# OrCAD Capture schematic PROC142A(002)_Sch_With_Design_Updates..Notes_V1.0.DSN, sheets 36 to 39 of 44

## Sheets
36 36. USB1 TYPE A: size C; title: USB1 TYPE-A
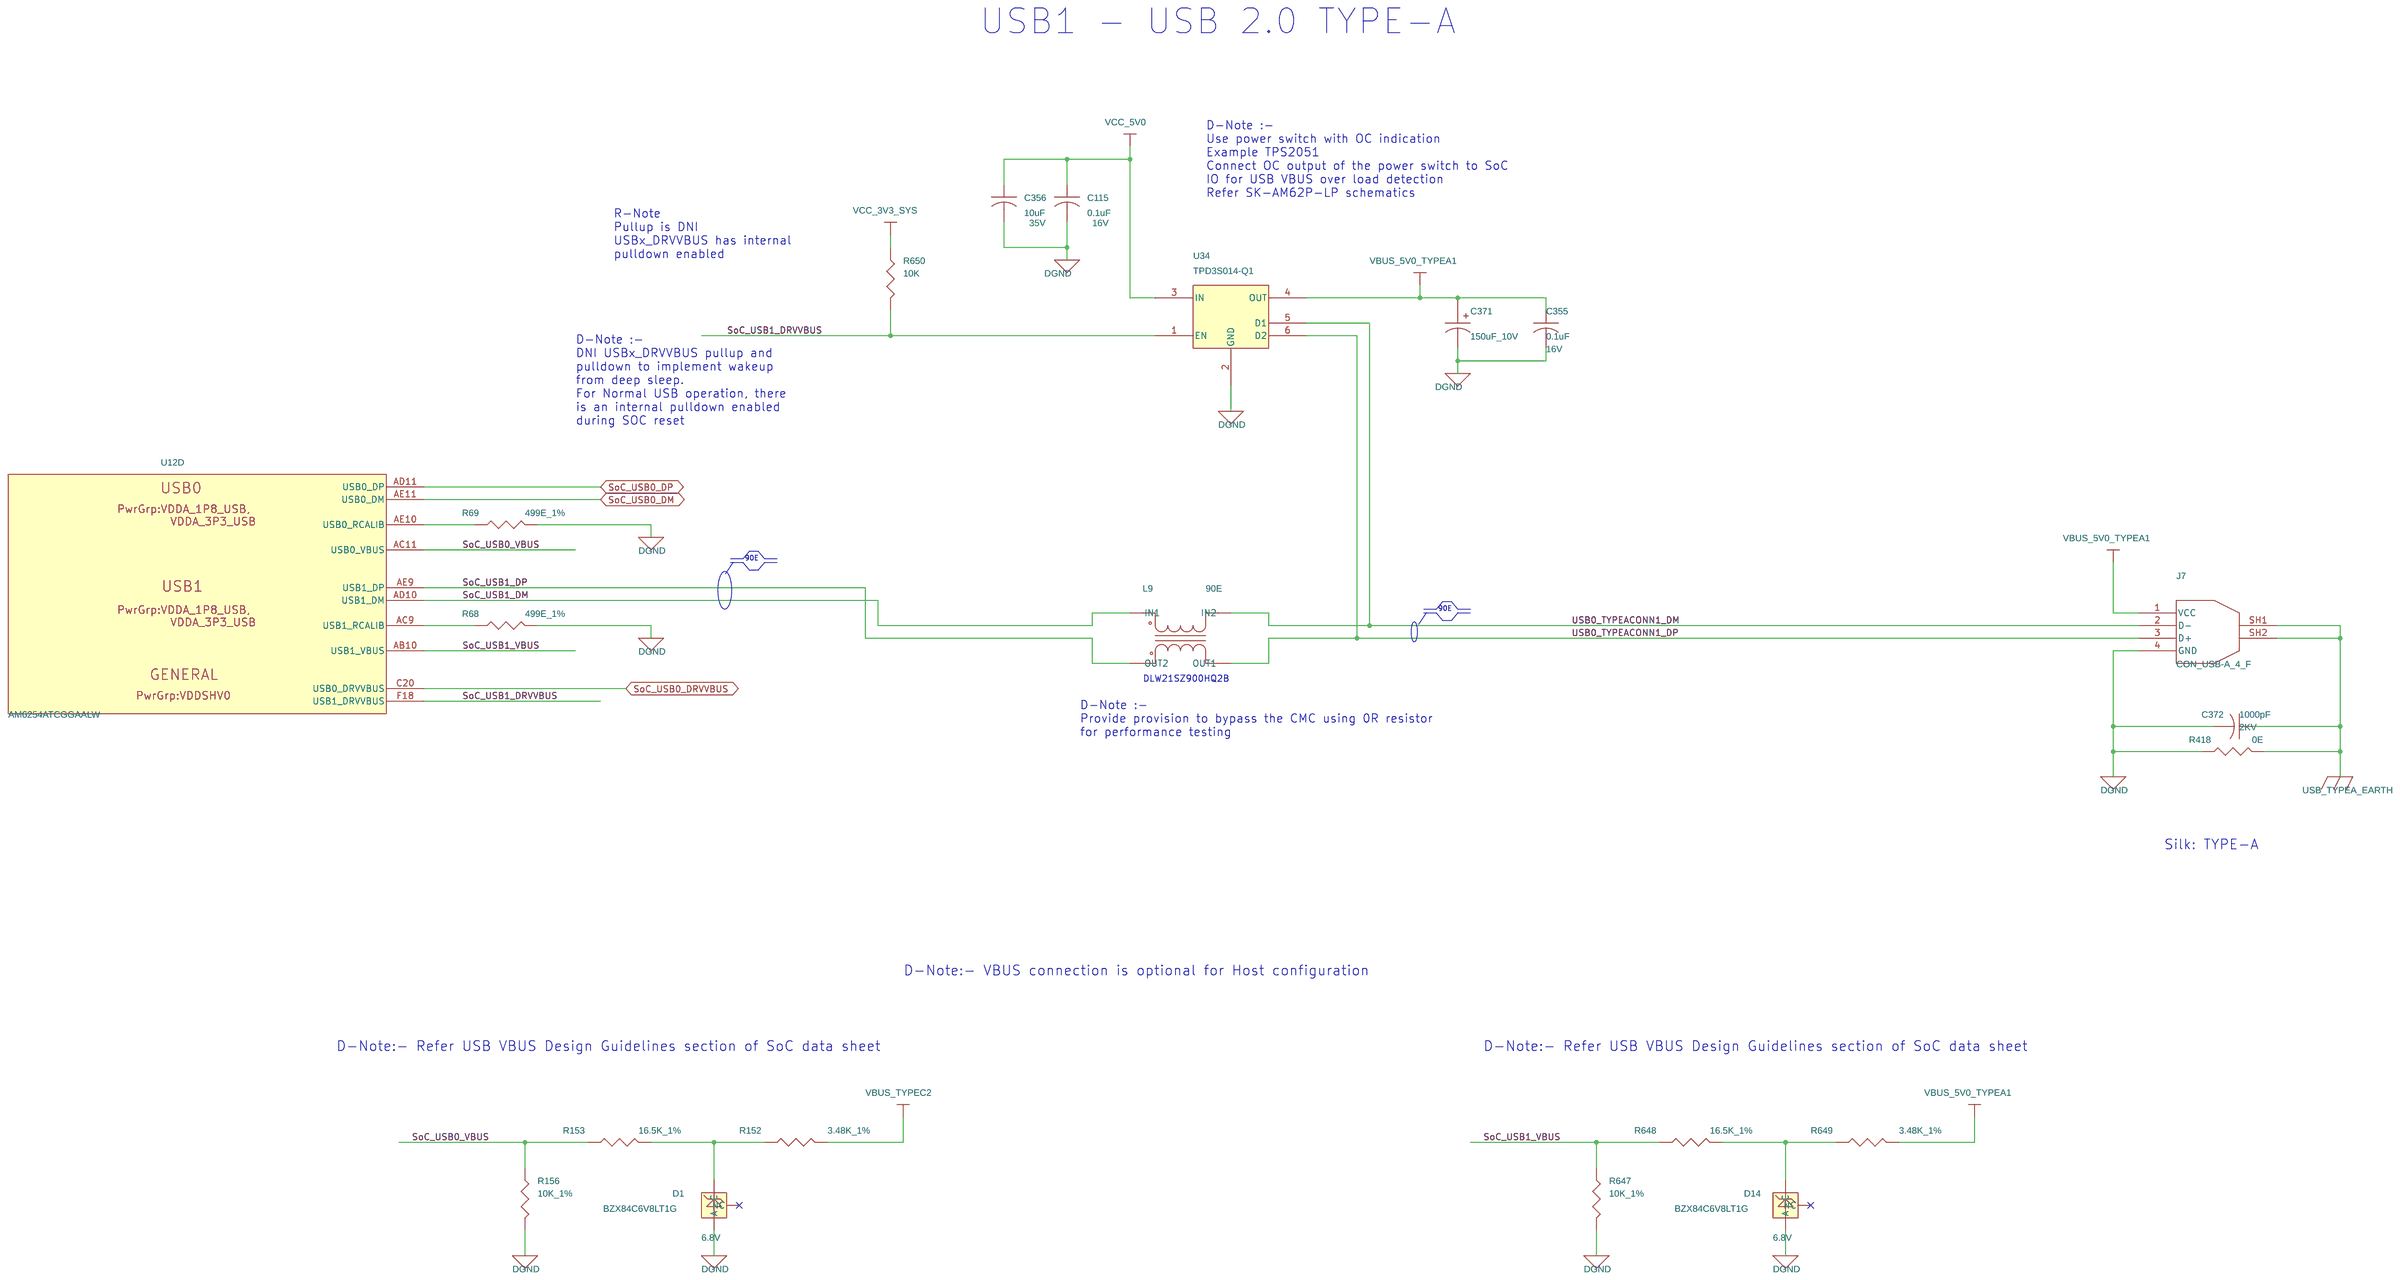
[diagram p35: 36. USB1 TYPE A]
37 37. OLDI DISPLAY INTERFACE: size C; title: OLDI DISPLAY INTERFACE
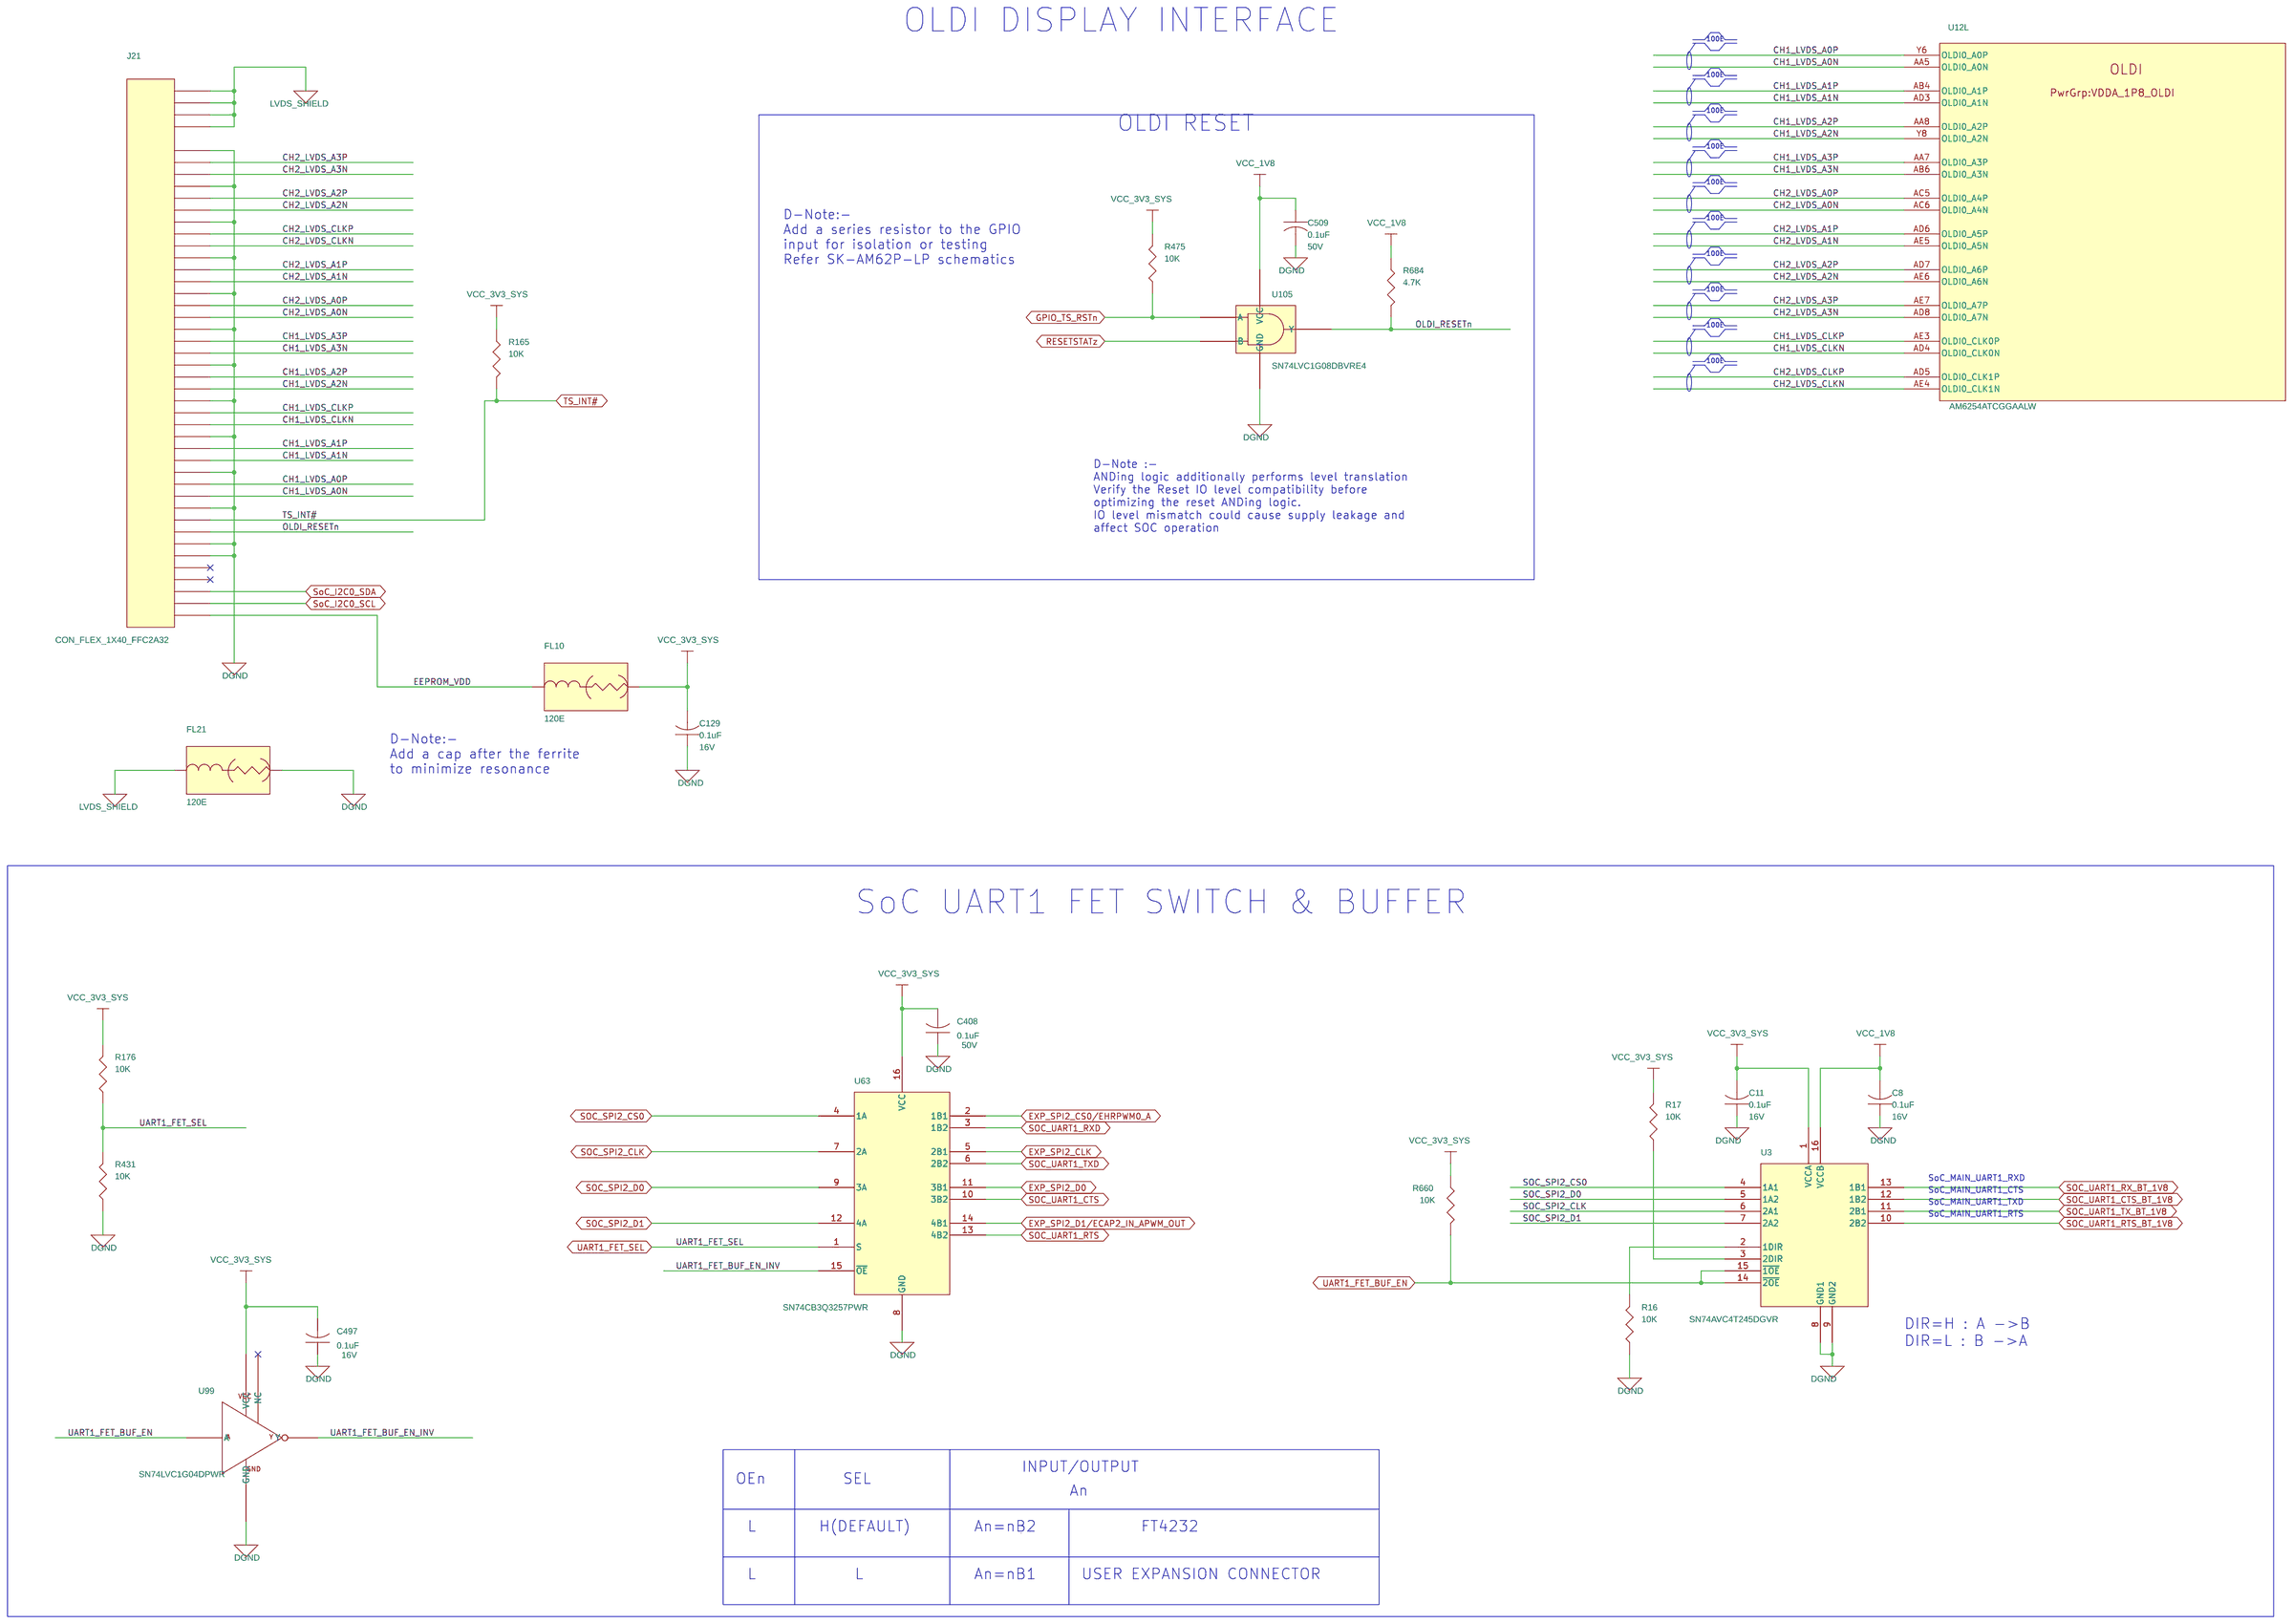
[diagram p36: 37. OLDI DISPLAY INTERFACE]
38 38. CSI INTERFACE & TEST LEDS: size C; title: CSI INTERFACE & USER TEST LEDS
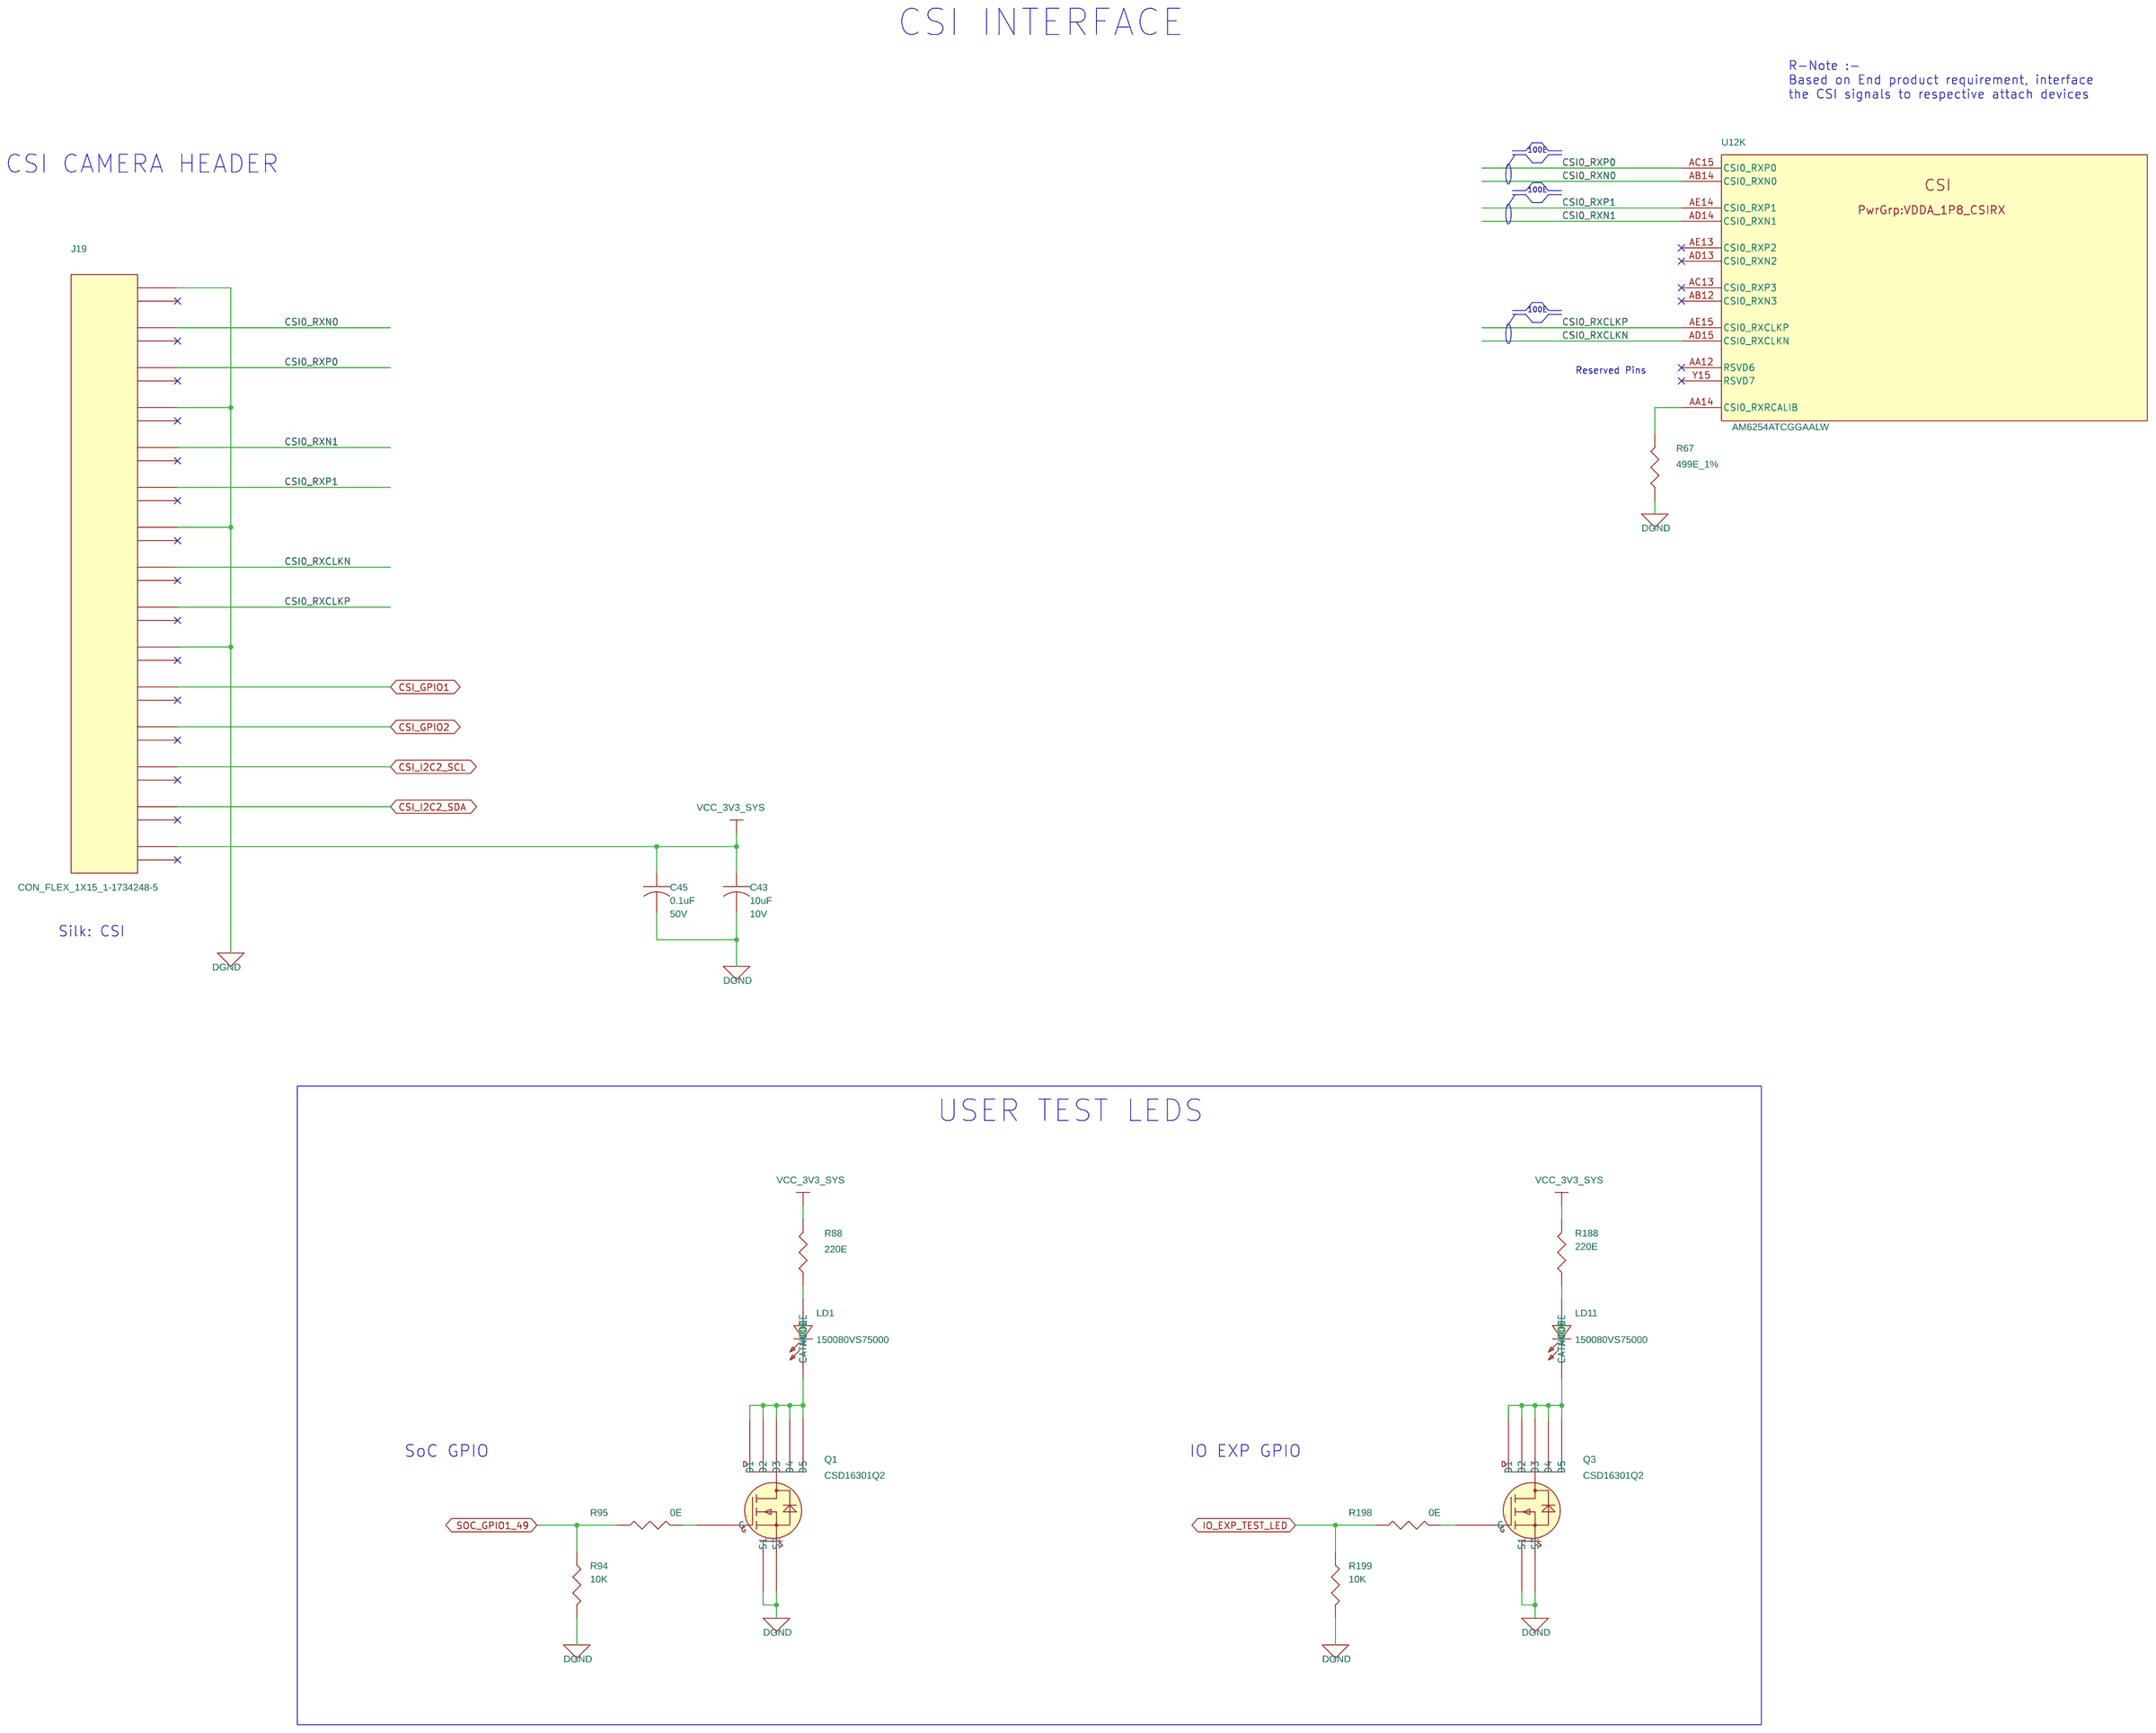
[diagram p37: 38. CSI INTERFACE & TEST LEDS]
39 39. IO EXPANDER: size C; title: IO EXPANDER

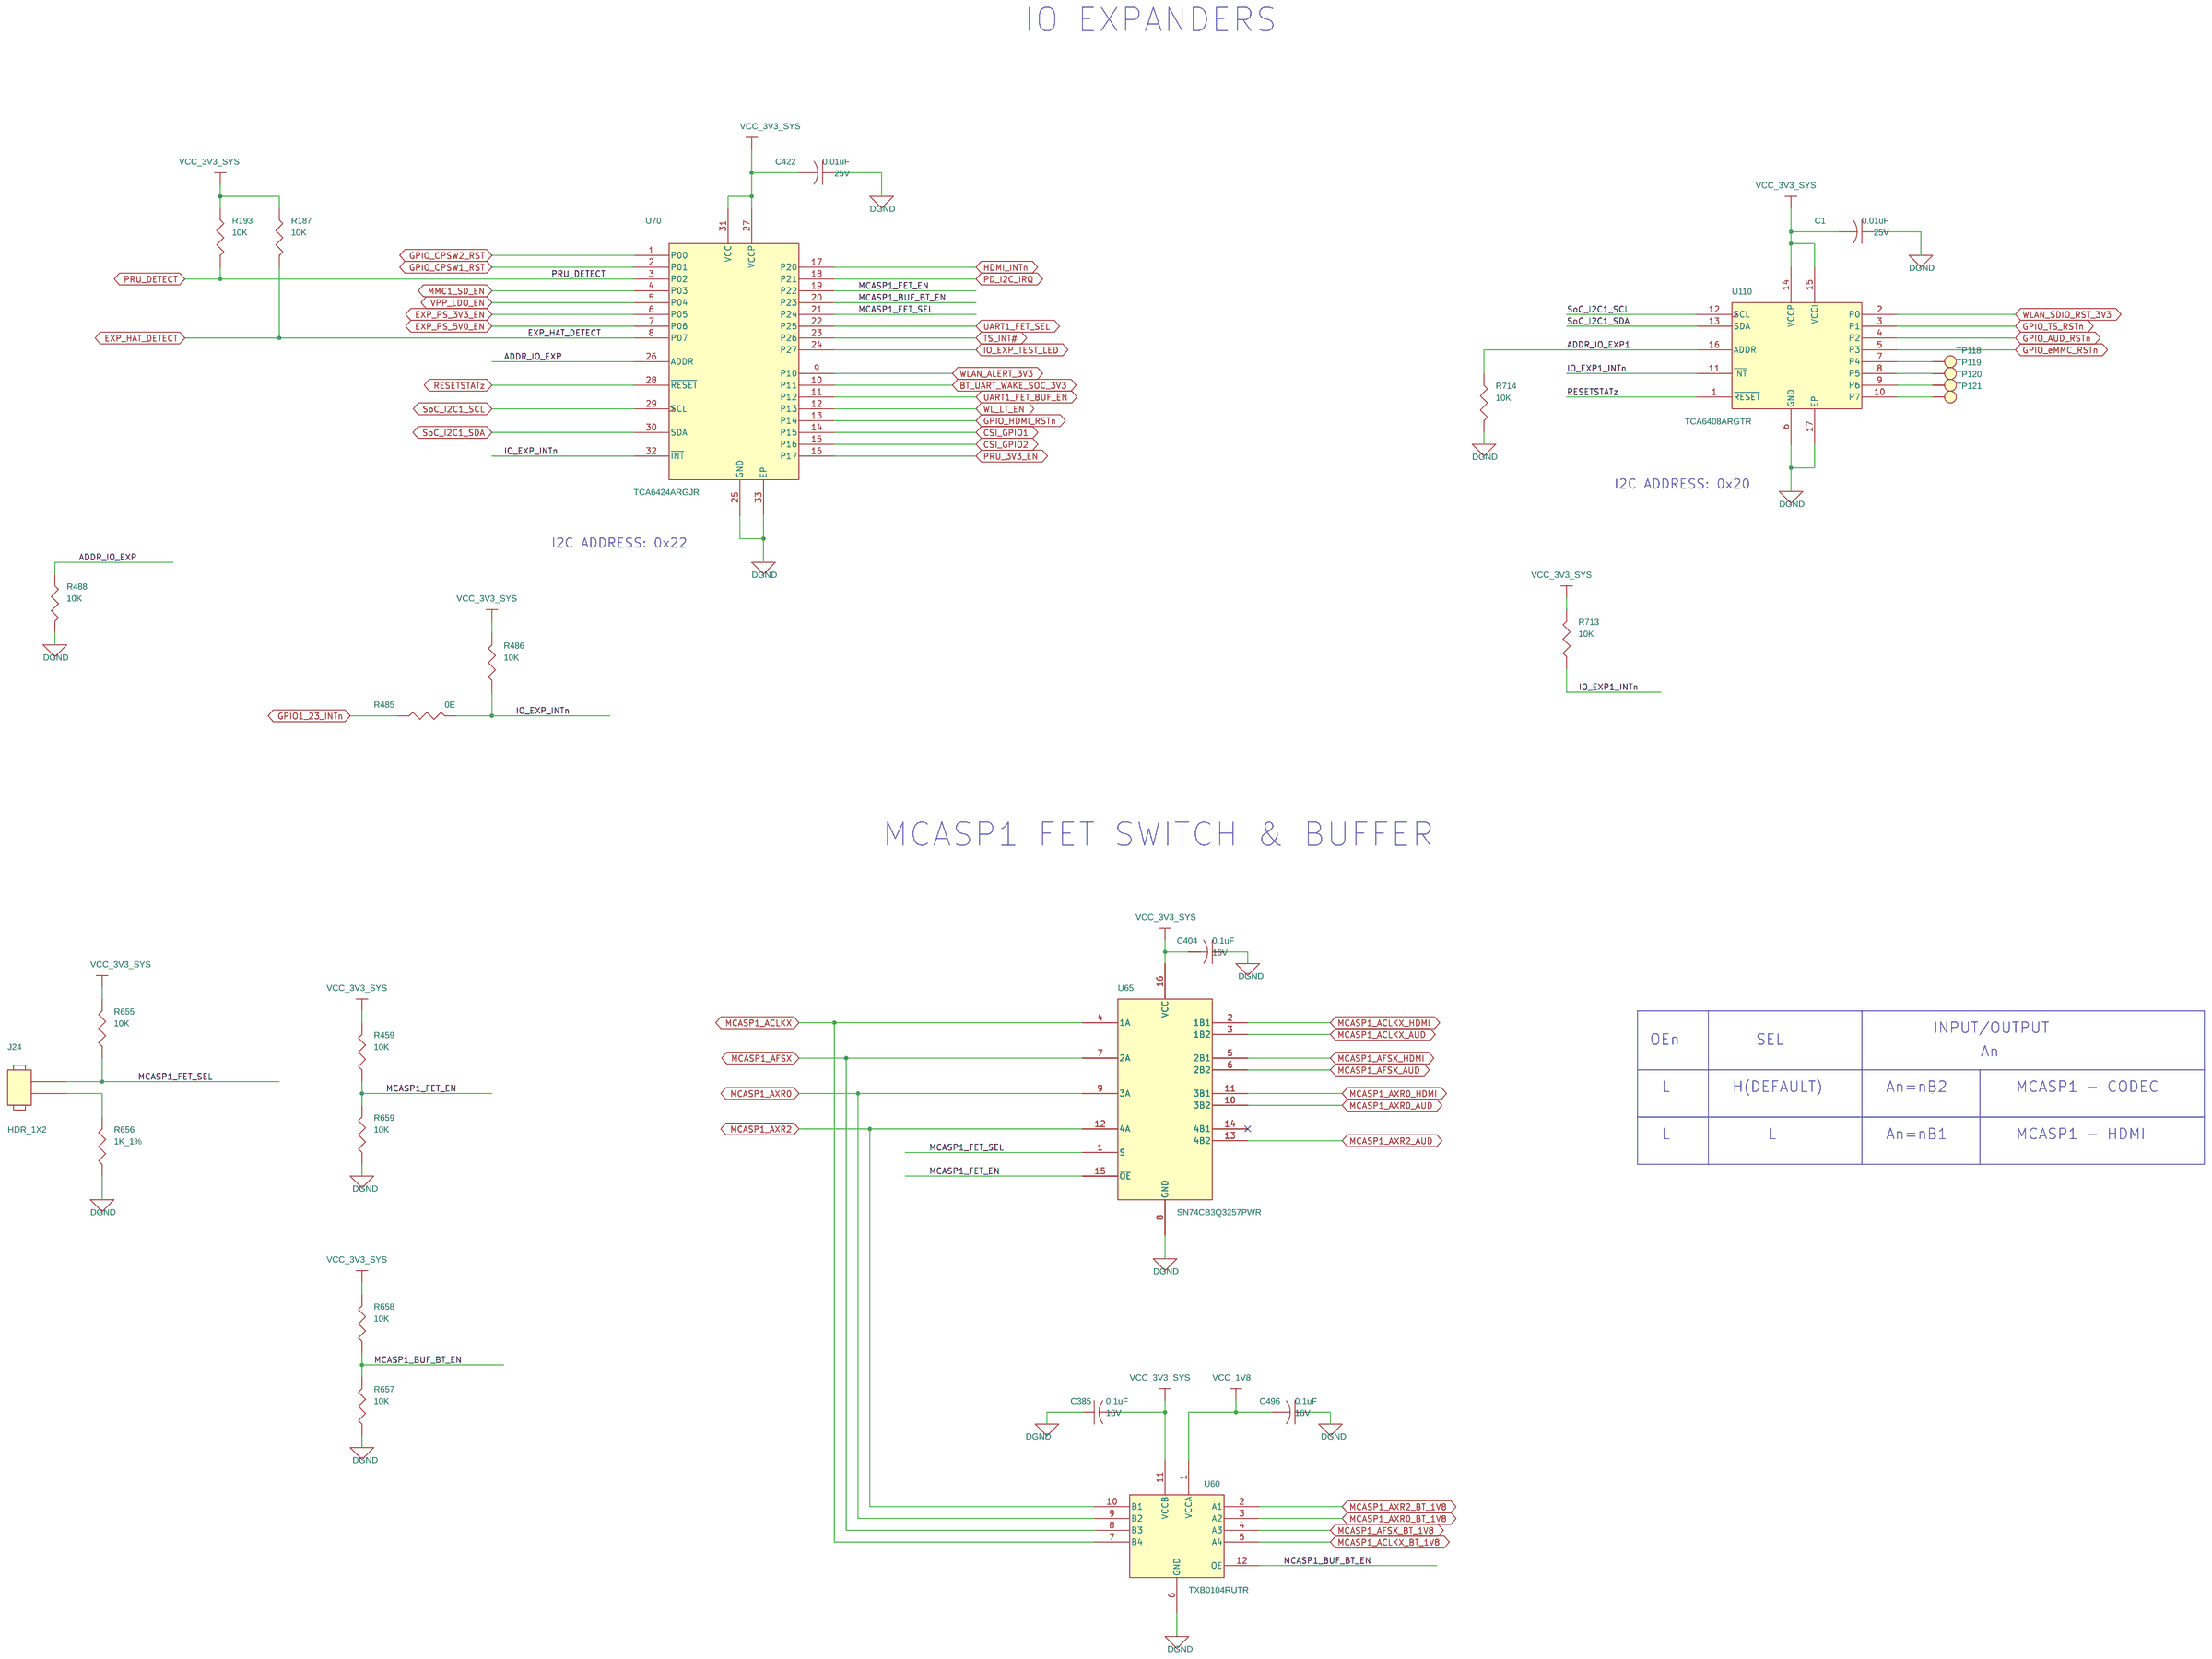
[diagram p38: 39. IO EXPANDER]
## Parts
sheet 36. USB1 TYPE A
C115  0.1uF  [CAP0201_0-5]
C355  0.1uF  [CAP0201_0-5]
C356  10uF  [CAP0603_1]
C371  150uF_10V  [CAPT7343D_3-25]
C372  1000pF  [CAP1206_1-75]
D1  BZX84C6V8LT1G  [SOT23-123_1-2]
D14  BZX84C6V8LT1G  [SOT23-123_1-2]
J7  CON_USB-A_4_F  [CON_USBA4_629104151_S_R_S_7-4]
L9  90E  [IND4_DLW21H_90X60_SMD_1-4]
R68  499E_1%  [RES0402_0-5]
R69  499E_1%  [RES0402_0-5]
R152  3.48K_1%  [RES0201_0-5]
R153  16.5K_1%  [RES0402_0-5]
R156  10K_1%  [RES0201_0-5]
R418  0E  [RES0603_0-75]
R647  10K_1%  [RES0201_0-5]
R648  16.5K_1%  [RES0402_0-5]
R649  3.48K_1%  [RES0201_0-5]
R650  10K  [RES0201_0-5]
U34  TPD3S014-Q1  [SOT23-6_1-5]
sheet 37. OLDI DISPLAY INTERFACE
C8  0.1uF  [CAP0201_0-5]
C11  0.1uF  [CAP0201_0-5]
C129  0.1uF  [CAP0201_0-5]
C408  0.1uF  [CAP0402_0-75]
C497  0.1uF  [CAP0201_0-5]
C509  0.1uF  [CAP0402_0-75]
FL10  120E  [EMIFIL_BLM15A_0402_0-6]
FL21  120E  [EMIFIL_BLM15A_0402_0-6]
J21  CON_FLEX_1X40_FFC2A32  [CON_FLEX1X40_FFC2A32-40-T_S_S_S_4-3]
R16  10K  [RES0201_0-5]
R17  10K  [RES0201_0-5]
R165  10K  [RES0201_0-5]
R176  10K  [RES0201_0-5]
R431  10K  [RES0201_0-5]
R475  10K  [RES0201_0-5]
R660  10K  [RES0201_0-5]
R684  4.7K  [RES0201_0-5]
U3  SN74AVC4T245DGVR  [TVSOP16_15-74_150X180]
U63  SN74CB3Q3257PWR  [TSSOP16_25-59_205X180]
U99  SN74LVC1G04DPWR  [X2SON5_TLV7021_30X30_0-4]
U105  SN74LVC1G08DBVRE4  [SOT23-5]
sheet 38. CSI INTERFACE & TEST LEDS
C43  10uF  [CAP0402_0-75]
C45  0.1uF  [CAP0402_0-75]
J19  CON_FLEX_1X15_1-1734248-5  [CON_FLEX1X15_1-1734248-5_S_S_S_7-7]
LD1  150080VS75000  [LED_150080VS75000_80X50_SMD_0-8]
LD11  150080VS75000  [LED_150080VS75000_80X50_SMD_0-8]
Q1  CSD16301Q2  [WSON6_CSD13202Q2_80X80_0-8]
Q3  CSD16301Q2  [WSON6_CSD13202Q2_80X80_0-8]
R67  499E_1%  [RES0402_0-5]
R88  220E  [RES0402_0-5]
R94  10K  [RES0201_0-5]
R95  0E  [RES0402_0-5]
R188  220E  [RES0402_0-5]
R198  0E  [RES0402_0-5]
R199  10K  [RES0201_0-5]
sheet 39. IO EXPANDER
C1  0.01uF  [CAP0201_0-5]
C385  0.1uF  [CAP0201_0-5]
C404  0.1uF  [CAP0201_0-5]
C422  0.01uF  [CAP0201_0-5]
C496  0.1uF  [CAP0201_0-5]
J24  HDR_1X2  [HDR_1X2_90120-0122_S_T_5-6]
R187  10K  [RES0201_0-5]
R193  10K  [RES0201_0-5]
R459  10K  [RES0201_0-5]
R485  0E  [RES0402_0-5]
R486  10K  [RES0201_0-5]
R488  10K  [RES0201_0-5]
R655  10K  [RES0201_0-5]
R656  1K_1%  [RES0402_0-5]
R657  10K  [RES0201_0-5]
R658  10K  [RES0201_0-5]
R659  10K  [RES0201_0-5]
R713  10K  [RES0201_0-5]
R714  10K  [RES0201_0-5]
TP118  TP20_SMD  [TP20_SMD]
TP119  TP20_SMD  [TP20_SMD]
TP120  TP20_SMD  [TP20_SMD]
TP121  TP20_SMD  [TP20_SMD]
U60  TXB0104RUTR  [UQFN12_TXB0104RUT_70X80_0-6]
U65  SN74CB3Q3257PWR  [TSSOP16_25-59_205X180]
U70  TCA6424ARGJR  [QFN32_19-68_200X200]
U110  TCA6408ARGTR  [QFN16_19-68_120X120_1_EP1-6]
sheet 42. OSCILLATOR
U12  AM6254ATCGGAALW  [BGA425_19-68_510X510_0-7]  (sections A,B,C,D,E,F,G,H,I,J,K,L,M,N,O,P,Q,R)

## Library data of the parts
C115 C355 = CAP: CAP CERAMIC 0.1uF 16V 10% X5R 0201; Chkd/date: MANIRAJA/230118; Crtd /date: MANIRAJA/230118; Custom_Duty: 15%; Customs_HS_Code: 85322990; Distributor_name: DIGIKEY; Distributor_part_number: 490-14305-1-ND; Footprint Path: Y:\MIS_DATABASE\Library\ALTIUM_TOOL\PCB_FOOTPRINTS\Altium_Footprint_Lib.PcbLib; Height: 0.33MM; Library Path: Y:\MIS_DATABASE\Library\ALTIUM_TOOL\SCHEMATICS_PARTS\MS_DISCRETE_Library.schlib; Mfr_name: MURATA; Mfr_part_number: GRM033R61C104KE14D; Mistral Part No: 120009030072-R; Package: 0201; Part_type: CAPACITORS\CERAMIC; Project: TI_MAXIE_CPB; RoHS: RoHS; Temperature: -55°C+85°C; Tolerance: 10%; Voltage: 16V; Wattage: NA; Weight: 0.33mg; Datasheet: Y:\MIS_DATABASE\DATASHEETS\CAPACITORS\GRM033R61C104KE14.PDF
C356 = CAP: CAP CERAMIC 10uF 35V 20% X5R 0603; Chkd/date: MANIRAJA/170519; Crtd /date: ALVY/160519; Custom_Duty: 15%; Customs_HS_Code: 85322990; Distributor_name: DIGIKEY; Distributor_part_number: 490-13248-1-ND; Footprint Path: Y:\MIS_DATABASE\Library\ALTIUM_TOOL\PCB_FOOTPRINTS\Altium_Footprint_Lib.PcbLib; Height: 1.00MM; Library Path: Y:\MIS_DATABASE\Library\ALTIUM_TOOL\SCHEMATICS_PARTS\MS_DISCRETE_Library.schlib; Mfr_name: MURATA; Mfr_part_number: GRM188R6YA106MA73D; Mistral Part No: 120019050016-R; Package: 0603; Part_type: CAPACITORS\CERAMIC; Project: BRUKER_SD820_COMMONDO; RoHS: RoHS; Temperature: -55°C+85°C; Tolerance: 20%; Voltage: 35V; Wattage: NA; Weight: 9mg; Datasheet: Y:\MIS_DATABASE\DATASHEETS\CAPACITORS\GRM188R6YA106MA73.PDF
C371 = CAP_POL: CAP TANTALUM 150uF 10V 10% ESR 600mE D7343; Chkd/date: ALVY/200921; Crtd /date: MANIRAJA/200921; Custom_Duty: 15%; Customs_HS_Code: 85322990; Distributor_name: DIGIKEY; Distributor_part_number: 718-1960-1-ND; Footprint Path: Y:\MIS_DATABASE\Library\ALTIUM_TOOL\PCB_FOOTPRINTS\Altium_Footprint_Lib.PcbLib; Height: 3.10MM; Library Path: Y:\MIS_DATABASE\Library\ALTIUM_TOOL\SCHEMATICS_PARTS\MS_DISCRETE_Library.schlib; Mfr_name: VISHAY; Mfr_part_number: 293D157X9010D2TE3; Mistral Part No: 120021090007-R; Package: D7343; Part_type: CAPACITORS\TANTALUM; Project: TI_AM62x SKEVM_BRD; RoHS: RoHS; Temperature: -55°C+125°C; Tolerance: 10%; Voltage: 10V; Wattage: NA; Weight: 400mg; Datasheet: Y:\MIS_DATABASE\DATASHEETS\CAPACITORS\293D_SER_MAR20.PDF
C372 = CAP: CAP CERAMIC 1000pF 2KV 10% X7R 1206; Chkd/date: SHREESHAIL/291106; Crtd /date: MAZHAR/281106; Custom_Duty: 15%; Customs_HS_Code: 85322990; Distributor_name: DIGIKEY; Distributor_part_number: 478-2956-1-ND; Footprint Path: Y:\MIS_DATABASE\Library\ALTIUM_TOOL\PCB_FOOTPRINTS\Altium_Footprint_Lib.PcbLib; Height: 1.52MM; Library Path: Y:\MIS_DATABASE\Library\ALTIUM_TOOL\SCHEMATICS_PARTS\MS_DISCRETE_Library.schlib; Mfr_name: AVX CORPORATION; Mfr_part_number: 1206GC102KAT1A; Mistral Part No: 120015080006-R; Package: 1206; Part_type: CAPACITORS\CERAMIC; Project: ADR1B; RoHS: RoHS; Temperature: -55°C+125°C; Tolerance: 10%; Voltage: 2KV; Wattage: NA; Weight: 16.2mg; Datasheet: Y:\MIS_DATABASE\DATASHEETS\CAPACITORS\AVX_HV-MLC.PDF
D1 D14 = DIODE_ZENER_SOT23_13: DIODE ZENER 250mW 6.8V SOT23-123; Chkd/date: MANIRAJA/031017; Crtd /date: MANIRAJA/031017; Custom_Duty: 15%; Customs_HS_Code: 85412900; Distributor_name: DIGIKEY; Distributor_part_number: BZX84C6V8LT1GOSCT-ND; Height: 1.11MM; Mfr_name: ON SEMICONDUCTOR; Mistral Part No: 130017100002-R; Package: SOT23-123; Part_type: DIODE\ZENER; Project: TI_MAXIE_CPB; RoHS: RoHS; Temperature: -65°C+150°C; Tolerance: NA; Voltage: 6.8V; Wattage: NA; Weight: 8mg; Datasheet: Y:\MIS_DATABASE\DATASHEETS\DISCRETES\DIODES\BZX84XX.PDF
J7 = CON_USB-A_4_2SH: CON USB-A TYPE 4POS FEMALE RT SMD; Chkd/date: MANIRAJA/271017; Crtd /date: MANIRAJA/271017; Custom_Duty: 24%; Customs_HS_Code: 85369090; Distributor_name: DIGIKEY; Distributor_part_number: 732-5969-1-ND; Height: 7.35MM; Mfr_name: WURTH ELECTRONICS; Mfr_part_number: 629104151021; Mistral Part No: 150017100042-R; Package: SMD; Part_type: CONNECTOR\USB; Project: TI_SVB_MAXWELL_SPM; RoHS: RoHS; Temperature: -40°C+85°C; Tolerance: NA; Voltage: NA; Wattage: NA; Weight: NA; Datasheet: Y:\MIS_DATABASE\DATASHEETS\CONNECTORS\629104151021.PDF
L9 = INDUCTOR_DLW31S: IND COMMON MODE CHOKE 90E 280mA SMD; Chkd/date: MANIRAJA/270619; Crtd /date: MANIRAJA/270619; Custom_Duty: 24%; Customs_HS_Code: 85437099; Distributor_name: NA; Distributor_part_number: NA; Footprint Path: Y:\MIS_DATABASE\Library\ALTIUM_TOOL\PCB_FOOTPRINTS\Altium_Footprint_Lib.PcbLib; Height: 1.40MM; Library Path: Y:\MIS_DATABASE\Library\ALTIUM_TOOL\SCHEMATICS_PARTS\MS_DISCRETE_Library.schlib; Mfr_name: MURATA; Mfr_part_number: DLW21SZ900HQ2B; Mistral Part No: 130019060035-R; Package: SMD; Part_type: INDUCTOR; Project: TI_J7ES_CP; RoHS: RoHS; Temperature: -40°C+105°C; Tolerance: NA; Voltage: NA; Wattage: NA; Weight: 11mg; Datasheet: Y:\MIS_DATABASE\DATASHEETS\DISCRETES\INDUCTORS\DLW21SZ900HQ2B.PDF
R67-R69 = RESISTOR: RES 499E 1/16W 1% 0402; Chkd/date: MANIRAJA/051020; Crtd /date: ALVY/051020; Custom_Duty: 15%; Customs_HS_Code: 85332119; Distributor_name: DIGIKEY; Distributor_part_number: 311-499LRCT-ND; Footprint Path: Y:\MIS_DATABASE\Library\ALTIUM_TOOL\PCB_FOOTPRINTS\Altium_Footprint_Lib.PcbLib; Height: 0.40MM; Library Path: Y:\MIS_DATABASE\Library\ALTIUM_TOOL\SCHEMATICS_PARTS\MS_DISCRETE_Library.schlib; Mfr_name: YAGEO AMERICA; Mfr_part_number: RC0402FR-07499RL; Mistral Part No: 110020080006-R; Package: 0402; Part_type: RESISTORS\FIXED; Project: AM64XX_EVM; RoHS: RoHS; Temperature: -55°C+155°C; Tolerance: 1%; Voltage: NA; Wattage: 1/16W; Weight: 0.65mg; Datasheet: Y:\MIS_DATABASE\DATASHEETS\RESISTORS\RCXXXXL-SER_MAR18.PDF
R152 R649 = RESISTOR: RES 3.48K 1/20W 1% 0201; Chkd/date: PRADEEP/281123; Crtd /date: TAMILARASU/071123; Custom_Duty: 15%; Customs_HS_Code: 85322990; Distributor_name: DIGIKEY; Distributor_part_number: P122951CT-ND; Footprint Path: Y:\MIS_DATABASE\Library\ALTIUM_TOOL\PCB_FOOTPRINTS\Altium_Footprint_Lib.PcbLib; Height: 0.26MM; Library Path: Y:\MIS_DATABASE\Library\ALTIUM_TOOL\SCHEMATICS_PARTS\MS_DISCRETE_Library.schlib; Mfr_name: PANASONIC-ECG; Mfr_part_number: ERJ-1GNF3481C; Mistral Part No: 110023110006-R; Package: 0201; Part_type: RESISTORS\FIXED; Project: AM62P SK; RoHS: RoHS; Temperature: -55°C+125°C; Tolerance: 0.01; Voltage: NA; Wattage: 1/20W; Weight: 0.15mg; Datasheet: Y:\MIS_DATABASE\DATASHEETS\RESISTORS\PAN-ERJSER_DEC22.PDF
R153 R648 = RESISTOR: RES 16.5K 1/16W 1% 0402; Chkd/date: ALVY/091220; Crtd /date: MANIRAJA/091220; Custom_Duty: 15%; Customs_HS_Code: 85332119; Distributor_name: DIGIKEY; Distributor_part_number: YAG3002CT-ND; Footprint Path: Y:\MIS_DATABASE\Library\ALTIUM_TOOL\PCB_FOOTPRINTS\Altium_Footprint_Lib.PcbLib; Height: 0.40MM; Library Path: Y:\MIS_DATABASE\Library\ALTIUM_TOOL\SCHEMATICS_PARTS\MS_DISCRETE_Library.schlib; Mfr_name: YAGEO AMERICA; Mfr_part_number: RC0402FR-0716K5L; Mistral Part No: 110020120011-R; Package: 0402; Part_type: RESISTORS\FIXED; Project: TI_AM243x LP EVM; RoHS: RoHS; Temperature: -55°C+155°C; Tolerance: 1%; Voltage: NA; Wattage: 1/16W; Weight: 0.65mg; Datasheet: Y:\MIS_DATABASE\DATASHEETS\RESISTORS\RCXXXXL-SER_MAR18.PDF
R156 R647 = RESISTOR: RES 10K 1/20W 1% 0201; Chkd/date: VASANTHA/270117; Crtd /date: MANIRAJA/270117; Custom_Duty: 15%; Customs_HS_Code: 85332119; Distributor_name: DIGIKEY; Distributor_part_number: 311-10.0KMCT-ND; Footprint Path: Y:\MIS_DATABASE\Library\ALTIUM_TOOL\PCB_FOOTPRINTS\Altium_Footprint_Lib.PcbLib; Height: 0.26MM; Library Path: Y:\MIS_DATABASE\Library\ALTIUM_TOOL\SCHEMATICS_PARTS\MS_DISCRETE_Library.schlib; Mfr_name: YAGEO AMERICA; Mfr_part_number: RC0201FR-0710KL; Mistral Part No: 110011040018-R; Package: 0201; Part_type: RESISTORS\FIXED; Project: GOLDEN-I LITE; RoHS: RoHS; Temperature: -55°C+125°C; Tolerance: 1%; Voltage: NA; Wattage: 1/20W; Weight: 0.17mg; Datasheet: Y:\MIS_DATABASE\DATASHEETS\RESISTORS\RCXXXXL-SER_MAR18.PDF
R418 = RESISTOR: RES 0E 1/10W 5% 0603; Chkd/date: MANIRAJA/051217; Crtd /date: BAVISH/180211; Custom_Duty: 15%; Customs_HS_Code: 85332119; Distributor_name: DIGIKEY; Distributor_part_number: 311-0.0GRCT-ND; Footprint Path: Y:\MIS_DATABASE\Library\ALTIUM_TOOL\PCB_FOOTPRINTS\Altium_Footprint_Lib.PcbLib; Height: 0.55MM; Library Path: Y:\MIS_DATABASE\Library\ALTIUM_TOOL\SCHEMATICS_PARTS\MS_DISCRETE_Library.schlib; Manufacturer: YAGEO AMERICA; Mfr_name: PANASONIC-ECG; Mfr_part_number: RC0603JR-070RL; Mistral Part No: 110011020013-R; Package: 0603; Part_type: RESISTORS\FIXED; Project: KENNEL; RoHS: RoHS; Temperature: -55°C+155°C; Tolerance: 5%; Voltage: NA; Wattage: 1/10W; Weight: 2mg; Datasheet: Y:\MIS_DATABASE\DATASHEETS\RESISTORS\RCXXXXL-SER_MAR18.PDF
R16 R17 R94 R165 R176 R187 R193 R199 R431 R459 R475 R486 R488 R650 R655 R657-R660 R713 R714 = RESISTOR: RES 10K 1/20W 5% 0201; Chkd/date: MANIRAJA/050517; Crtd /date: MANIRAJA/050517; Custom_Duty: 15%; Customs_HS_Code: 85332119; Distributor_name: DIGIKEY; Distributor_part_number: 311-10KNCT-ND; Footprint Path: Y:\MIS_DATABASE\Library\ALTIUM_TOOL\PCB_FOOTPRINTS\Altium_Footprint_Lib.PcbLib; Height: 0.26MM; Library Path: Y:\MIS_DATABASE\Library\ALTIUM_TOOL\SCHEMATICS_PARTS\MS_DISCRETE_Library.schlib; Mfr_name: YAGEO AMERICA; Mfr_part_number: RC0201JR-0710KL; Mistral Part No: 110010070051-R; Package: 0201; Part_type: RESISTORS\FIXED; Project: GOLDEN-I LITE; RoHS: RoHS; Temperature: -55°C+125°C; Tolerance: 5%; Voltage: NA; Wattage: 1/20W; Weight: 0.17mg; Datasheet: Y:\MIS_DATABASE\DATASHEETS\RESISTORS\RCXXXXL-SER_MAR18.PDF
U34 = TPD3S014D_SOT23-6: IC ESD PROTECTION FOR AUTO USB PORT WITH CURRENT LIMIT SWITCH SOT23-6; Chkd/date: MANIRAJA/180918; Crtd /date: ALVY/180918; Custom_Duty: 15%; Customs_HS_Code: 85423100; Distributor_name: DIGIKEY; Distributor_part_number: 296-44163-1-ND; Footprint Path: Y:\MIS_DATABASE\Library\ALTIUM_TOOL\PCB_FOOTPRINTS\Altium_Footprint_Lib.PcbLib; Height: 1.45MM; Library Path: Y:\MIS_DATABASE\Library\ALTIUM_TOOL\SCHEMATICS_PARTS\MS_MISCINTERFACE_Library.schlib; Mfr_name: TEXAS INSTRUMENTS; Mfr_part_number: TPD3S014TDBVRQ1; Mistral Part No: 141018090014-R; Package: SOT23-6; Part_type: ICS\INTERFACE; Project: TI_J7ES_EVM_CP; RoHS: RoHS; Temperature: -40°C+105°C; Tolerance: NA; Voltage: NA; Wattage: NA; Weight: NA; Datasheet: Y:\MIS_DATABASE\DATASHEETS\ICS\INTERFACE\TPD3S014-Q1.PDF
C8 C11 C129 C385 C404 C496 C497 = CAP: CAP CERAMIC 0.1uF 16V 10% X5R 0201; Alt_Mfr_name: YAGEO AMERICA; Alt_Mfr_part_number: CC0402KRX5R8BB104; Chkd/date: MANIRAJA/230118; Crtd /date: MANIRAJA/230118; Custom_Duty: 15%; Customs_HS_Code: 85322990; Distributor_name: DIGIKEY; Distributor_part_number: 490-14305-1-ND; Footprint Path: Y:\MIS_DATABASE\Library\ALTIUM_TOOL\PCB_FOOTPRINTS\Altium_Footprint_Lib.PcbLib; Height: 0.33MM; Library Path: Y:\MIS_DATABASE\Library\ALTIUM_TOOL\SCHEMATICS_PARTS\MS_DISCRETE_Library.schlib; Mfr_name: MURATA; Mfr_part_number: GRM033R61C104KE14D; Mistral Part No: 120009030072-R; Package: 0201; Part_type: CAPACITORS\CERAMIC; Project: TI_MAXIE_CPB; RoHS: RoHS; Temperature: -55°C+85°C; Tolerance: 10%; Voltage: 16V; Wattage: NA; Weight: 0.33mg; Datasheet: Y:\MIS_DATABASE\DATASHEETS\CAPACITORS\GRM033R61C104KE14.PDF
C45 C408 C509 = CAP: CAP CERAMIC 0.1uF 50V 10% X7R 0402; Alt_Mfr_name: YAGEO AMERICA; Alt_Mfr_part_number: CC0402KRX5R8BB104; Chkd/date: MANIRAJA/261020; Crtd /date: ALVY/211020; Custom_Duty: 15%; Customs_HS_Code: 85322990; Distributor_name: DIGIKEY; Distributor_part_number: 490-10700-1-ND; Footprint Path: Y:\MIS_DATABASE\Library\ALTIUM_TOOL\PCB_FOOTPRINTS\Altium_Footprint_Lib.PcbLib; Height: 0.55MM; Library Path: Y:\MIS_DATABASE\Library\ALTIUM_TOOL\SCHEMATICS_PARTS\MS_DISCRETE_Library.schlib; Mfr_name: MURATA; Mfr_part_number: GRM155R71H104KE14D; Mistral Part No: 120011100014-R; Package: 0402; Part_type: CAPACITORS\CERAMIC; Project: J7_CP; RoHS: RoHS; Temperature: -55°C+125°C; Tolerance: 10%; Voltage: 50V; Wattage: NA; Weight: 3.1mg; Datasheet: Y:\MIS_DATABASE\DATASHEETS\CAPACITORS\GRM155R71H104KE14.PDF
FL10 FL21 = EMIFILTER_IND: IND FERRITE BEAD CHIP 120E 2A 0402; Chkd/date: NAVEED/241114; Crtd /date: USMAN/170613; Custom_Duty: 24%; Customs_HS_Code: 85369090; Distributor_name: DIGIKEY; Distributor_part_number: 490-9656-1-ND; Footprint Path: Y:\MIS_DATABASE\Library\ALTIUM_TOOL\PCB_FOOTPRINTS\Altium_Footprint_Lib.PcbLib; Height: 0.55MM; Library Path: Y:\MIS_DATABASE\Library\ALTIUM_TOOL\SCHEMATICS_PARTS\MS_FILTER_Library.schlib; Mfr_name: MURATA; Mfr_part_number: BLM15PX121SN1D; Mistral Part No: 130013060022-R; Package: 0402; Part_type: INDUCTOR; Project: GEN_3-8; RoHS: RoHS; Temperature: -55°C+125°C; Tolerance: 25%; Voltage: NA; Wattage: NA; Weight: 1mg; Datasheet: Y:\MIS_DATABASE\DATASHEETS\DISCRETES\INDUCTORS\BLM15-SN1-SER.PDF
J21 = CON_FLEX_40X1_SH4: CON FPC 1X40 0.50MM PITCH FEMALE ST SMD; Chkd/date: MANIRAJA/061021; Crtd /date: ALVY/041021; Custom_Duty: 24%; Customs_HS_Code: 85369090; Distributor_name: DIGIKEY; Distributor_part_number: 2073-FFC2A32-40-TCT-ND; Footprint Path: Y:\MIS_DATABASE\Library\ALTIUM_TOOL\PCB_FOOTPRINTS\Altium_Footprint_Lib.PcbLib; Height: 4.25MM; Library Path: Y:\MIS_DATABASE\Library\ALTIUM_TOOL\SCHEMATICS_PARTS\MS_CONNECTOR_Library.schlib; Mfr_name: GCT; Mfr_part_number: FFC2A32-40-T; Mistral Part No: 150021100004-R; Package: SMD; Part_type: CONNECTOR\FPC; Project: TI_AM62x SKEVM_BRD; RoHS: RoHS; Temperature: -25°C+85°C; Tolerance: NA; Voltage: NA; Wattage: NA; Weight: 710mg; Datasheet: Y:\MIS_DATABASE\DATASHEETS\CONNECTORS\FFC2A32.PDF
R684 = RESISTOR: RES 4.7K 1/20W 5% 0201; Chkd/date: MANIRAJA/200921; Crtd /date: ALVY/200921; Custom_Duty: 15%; Customs_HS_Code: 85332119; Distributor_name: DIGIKEY; Distributor_part_number: 311-4.7KNCT-ND; Footprint Path: Y:\MIS_DATABASE\Library\ALTIUM_TOOL\PCB_FOOTPRINTS\Altium_Footprint_Lib.PcbLib; Height: 0.26MM; Library Path: Y:\MIS_DATABASE\Library\ALTIUM_TOOL\SCHEMATICS_PARTS\MS_DISCRETE_Library.schlib; Mfr_name: YAGEO AMERICA; Mfr_part_number: RC0201JR-074K7L; Mistral Part No: 110021090007-R; Package: 0201; Part_type: RESISTORS\FIXED; Project: TI_AM62x SKEVM_BRD; RoHS: RoHS; Temperature: -55°C+125°C; Tolerance: 5%; Voltage: NA; Wattage: 1/20W; Weight: 0.17mg; Datasheet: Y:\MIS_DATABASE\DATASHEETS\RESISTORS\RCXXXXL-SER_MAR18.PDF
U3 = SN74AVC4T245DGVR_TVSOP16: IC 4-BIT DUAL SUPPLY BUS TRANSCEIVER TVSOP16; Chkd/date: SUHAS/251010; Crtd /date: MAZHAR/201109; Custom_Duty: 15%; Customs_HS_Code: 85423100; Distributor_name: DIGIKEY; Distributor_part_number: 296-18054-1-ND; Height: 1.20MM; Mfr_name: TEXAS INSTRUMENTS; Mistral Part No: 141009110005-P; Package: TVSOP16; Part_type: ICS\DIGITAL\COMBINATIONAL; Project: GOLDEN-I; RoHS: Sb/ Br FREE; Temperature: -40°C+85°C; Datasheet: Y:\MIS_DATABASE\DATASHEETS\ICS\DIGITAL\BUSTRANSCEIVER\SN74AVC4T245.PDF
U63 = SN74CB3Q3257PWR_TSSOP16: IC 4BIT 1-OF-2 FET MULTIPLEXER/DEMULTIPLEXER TSSOP16; Chkd/date: SUHAS/251010; Crtd /date: USMAN/060109; Custom_Duty: 15%; Customs_HS_Code: 85423100; Distributor_name: DIGIKEY; Distributor_part_number: 296-19138-1-ND; Height: 1.20MM; Mfr_name: TEXAS INSTRUMENTS; Mistral Part No: 141009030117-R; Package: TSSOP16; Part_type: ICS\DIGITAL\COMBINATIONAL; Project: OMAP_EVM; RoHS: Sb/ Br FREE; Temperature: -40°C+85°C; Datasheet: Y:\MIS_DATABASE\DATASHEETS\ICS\DIGITAL\COMBINATIONAL\SN74CB3Q3257.PDF
U99 = SN74LVC1G04DCKR_SC70-5: IC SINGLE INVERTER GATE X2SON5; Chkd/date: MANIRAJA/141020; Crtd /date: ALVY/131020; Custom_Duty: 15%; Customs_HS_Code: 85423100; Distributor_name: DIGIKEY; Distributor_part_number: 296-37758-1-ND; Footprint Path: Y:\MIS_DATABASE\Library\ALTIUM_TOOL\PCB_FOOTPRINTS\Altium_Footprint_Lib.PcbLib; Height: 0.40MM; Library Path: Y:\MIS_DATABASE\Library\ALTIUM_TOOL\SCHEMATICS_PARTS\MS_GATE_Library.schlib; Mfr_name: TEXAS INSTRUMENTS; Mistral Part No: 141020100010-R; Package: X2SON5; Part_type: ICS\DIGITAL\GATES; Project: AM64X_SKEVM; RoHS: RoHS; Temperature: -40°C+125°C; Tolerance: NA; Voltage: NA; Wattage: NA; Weight: 0.6mg; Datasheet: Y:\MIS_DATABASE\DATASHEETS\ICS\DIGITAL\GATES\SN74LVC1G04XX.PDF
U105 = SN74LVC1G08DBVRE4_SOT23-5: IC SINGLE 2-INPUT POSITIVE AND GATE SOT23-5; Chkd/date: SUHAS/221010; Crtd /date: USMAN/151008; Custom_Duty: 15%; Customs_HS_Code: 85423100; Distributor_name: DIGIKEY; Distributor_part_number: SN74LVC1G08DBVRE4-ND; Height: 1.45MM; Mfr_name: TEXAS INSTRUMENTS; Mistral Part No: 141009060026-R; Part_type: ICS\DIGITAL\GATES; Project: KHAN_MAIN; RoHS: Sb/ Br FREE; Temperature: -40°C+85°C; Datasheet: Y:\MIS_DATABASE\DATASHEETS\ICS\DIGITAL\GATES\SN74LVC1G08.PDF
C43 = CAP: CAP CERAMIC 10uF 10V 20% X5R 0402; Chkd/date: MANIRAJA/300520; Crtd /date: ALVY/260520; Custom_Duty: 15%; Customs_HS_Code: 85322990; Distributor_name: DIGIKEY; Distributor_part_number: 490-GRM155R61A106ME11DTR-ND; Footprint Path: Y:\MIS_DATABASE\Library\ALTIUM_TOOL\PCB_FOOTPRINTS\Altium_Footprint_Lib.PcbLib; Height: 0.55MM; Library Path: Y:\MIS_DATABASE\Library\ALTIUM_TOOL\SCHEMATICS_PARTS\MS_DISCRETE_Library.schlib; Mfr_name: MURATA; Mfr_part_number: GRM155R61A106ME11D; Mistral Part No: 120013110019-R; Package: 0402; Part_type: CAPACITORS\CERAMIC; Project: QCS610_NANOSOM; RoHS: RoHS; Temperature: -55°C+85°C; Tolerance: 20%; Voltage: 10V; Wattage: NA; Weight: 3.1mg; Datasheet: Y:\MIS_DATABASE\DATASHEETS\CAPACITORS\MURATA-GXX-SER_NOV17.PDF
J19 = CON_FLEX_15X1_1-1734248-5: CON FPC 1X15 1.00MM PITCH FEMALE ST SMD; Chkd/date: ALVY/030620; Crtd /date: ALVY/030620; Custom_Duty: 24%; Customs_HS_Code: 85369090; Distributor_name: DIGIKEY; Distributor_part_number: A101418CT-ND; Footprint Path: Y:\MIS_DATABASE\Library\ALTIUM_TOOL\PCB_FOOTPRINTS\Altium_Footprint_Lib.PcbLib; Height: 7.70MM; Library Path: Y:\MIS_DATABASE\Library\ALTIUM_TOOL\SCHEMATICS_PARTS\MS_CONNECTOR_Library.schlib; Mfr_name: TE CONNECTIVITY; Mfr_part_number: 1-1734248-5; Mistral Part No: 150020060004-R; Package: SMD; Part_type: CONNECTOR\FPC; Project: JETSON_CARRIER_BRD; RoHS: RoHS; Temperature: -20°C+85°C; Tolerance: NA; Voltage: NA; Wattage: NA; Weight: 612mg; Datasheet: Y:\MIS_DATABASE\DATASHEETS\CONNECTORS\1734248.PDF
LD1 LD11 = DIODE_LED: DIODE LED BRIGHT GREEN SMD; Chkd/date: MANIRAJA/180820; Crtd /date: ALVY/180820; Custom_Duty: 24%; Customs_HS_Code: 85439000; Distributor_name: DIGIKEY; Distributor_part_number: 732-4986-1-ND; Footprint Path: Y:\MIS_DATABASE\Library\ALTIUM_TOOL\PCB_FOOTPRINTS\Altium_Footprint_Lib.PcbLib; Height: 0.80MM; Library Path: Y:\MIS_DATABASE\Library\ALTIUM_TOOL\SCHEMATICS_PARTS\MS_OPTO_Library.schlib; Mfr_name: WURTH ELECTRONICS; Mistral Part No: 130020080012-R; Package: SMD; Part_type: OPTO\LED; Project: AM64x_EVM_BRD; RoHS: RoHS; Temperature: -40°C+85°C; Tolerance: NA; Voltage: NA; Wattage: NA; Weight: 10mg; Datasheet: Y:\MIS_DATABASE\DATASHEETS\DISCRETES\LEDS\150080VS75000.PDF
Q1 Q3 = MOSFET_CSD17313Q2: IC MOSFET N-CHANNEL NEXFET 25V WSON6; Chkd/date: ALVY/071220; Crtd /date: MANIRAJA/071220; Custom_Duty: 15%; Customs_HS_Code: 85423100; Distributor_name: DIGIKEY; Distributor_part_number: 296-25260-1-ND; Footprint Path: Y:\MIS_DATABASE\Library\ALTIUM_TOOL\PCB_FOOTPRINTS\Altium_Footprint_Lib.PcbLib; Height: 0.80MM; Library Path: Y:\MIS_DATABASE\Library\ALTIUM_TOOL\SCHEMATICS_PARTS\MS_MOSFET_Library.schlib; Mfr_name: TEXAS INSTRUMENTS; Mistral Part No: 142020120008-R; Package: WSON6; Part_type: ICS\POWER\MOSFET; Project: TI_AM243x LP EVM; RoHS: RoHS; Temperature: -55°C+150°C; Tolerance: NA; Voltage: NA; Wattage: NA; Weight: 8.7mg; Datasheet: Y:\MIS_DATABASE\DATASHEETS\ICS\POWER\CSD16301Q2.PDF
R88 R188 = RESISTOR: RES 220E 1/10W 5% 0402; Chkd/date: VASANTHA/291216; Crtd /date: GEETHA/260406; Custom_Duty: 15%; Customs_HS_Code: 85332119; Distributor_name: DIGIKEY; Distributor_part_number: P220JCT-ND; Footprint Path: Y:\MIS_DATABASE\Library\ALTIUM_TOOL\PCB_FOOTPRINTS\Altium_Footprint_Lib.PcbLib; Height: 0.40MM; Library Path: Y:\MIS_DATABASE\Library\ALTIUM_TOOL\SCHEMATICS_PARTS\MS_DISCRETE_Library.schlib; Mfr_name: PANASONIC-ECG; Mfr_part_number: ERJ-2GEJ221X; Mistral Part No: 110009030506-R; Package: 0402; Part_type: RESISTORS\FIXED; Project: RED EYE; RoHS: RoHS; Temperature: -55°C+155°C; Tolerance: 5%; Voltage: NA; Wattage: 1/10W; Weight: 0.8mg; Datasheet: Y:\MIS_DATABASE\DATASHEETS\RESISTORS\PAN-ERJSER_NOV17.PDF
R95 R198 R485 = RESISTOR: RES 0E 1/16W JUMPER 0402; Chkd/date: VASANTHA/201216; Crtd /date: MUDDU/190810; Custom_Duty: 15%; Customs_HS_Code: 85332119; Distributor_name: DIGIKEY; Distributor_part_number: 541-0.0JCT-ND; Footprint Path: Y:\MIS_DATABASE\Library\ALTIUM_TOOL\PCB_FOOTPRINTS\Altium_Footprint_Lib.PcbLib; Height: 0.40MM; Library Path: Y:\MIS_DATABASE\Library\ALTIUM_TOOL\SCHEMATICS_PARTS\MS_DISCRETE_Library.schlib; Mfr_name: VISHAY; Mfr_part_number: CRCW04020000Z0ED; Mistral Part No: 110010080019-R; Package: 0402; Part_type: RESISTORS\FIXED; Project: PB_BUGBASE; RoHS: RoHS; Temperature: -55°C+155°C; Tolerance: NA; Voltage: NA; Wattage: 1/16W; Weight: 0.65mg; Datasheet: Y:\MIS_DATABASE\DATASHEETS\RESISTORS\CRCW0603.PDF
C1 C422 = CAP: CAP CERAMIC 0.01uF 25V 10% X5R 0201; Chkd/date: MANIRAJA/230118; Crtd /date: MANIRAJA/230118; Custom_Duty: 15%; Customs_HS_Code: 85322990; Distributor_name: DIGIKEY; Distributor_part_number: GRM033R61E103KA12J-ND; Footprint Path: Y:\MIS_DATABASE\Library\ALTIUM_TOOL\PCB_FOOTPRINTS\Altium_Footprint_Lib.PcbLib; Height: 0.33MM; Library Path: Y:\MIS_DATABASE\Library\ALTIUM_TOOL\SCHEMATICS_PARTS\MS_DISCRETE_Library.schlib; Mfr_name: MURATA; Mfr_part_number: GRM033R61E103KA12J; Mistral Part No: 120018010007-R; Package: 0201; Part_type: CAPACITORS\CERAMIC; Project: TI_MAXIE_CPB; RoHS: RoHS; Temperature: -55°C+85°C; Tolerance: 10%; Voltage: 25V; Wattage: NA; Weight: 0.33mg; Datasheet: Y:\MIS_DATABASE\DATASHEETS\CAPACITORS\GRM033R61E103KA12.PDF
J24 = HEADER_2X1: CON HDR 1X2 2.54MM PITCH ST TH; Chkd/date: NAVEED/210714; Crtd /date: USMAN/031012; Custom_Duty: 24%; Customs_HS_Code: 85369090; Distributor_name: DIGIKEY; Distributor_part_number: WM8072-ND; Footprint Path: Y:\MIS_DATABASE\Library\ALTIUM_TOOL\PCB_FOOTPRINTS\Altium_Footprint_Lib.PcbLib; Height: 5.60MM; Library Path: Y:\MIS_DATABASE\Library\ALTIUM_TOOL\SCHEMATICS_PARTS\MS_CONNECTOR_Library.schlib; Mfr_name: MOLEX; Mfr_part_number: 90120-0122; Mistral Part No: 150012100005-R; Package: THRU-HOLE; Part_type: CONNECTOR\HEADERS; Project: NPOL_FEP; RoHS: RoHS; Temperature: -55°C+125°C; Tolerance: NA; Voltage: NA; Wattage: NA; Weight: 122mg; Datasheet: Y:\MIS_DATABASE\DATASHEETS\CONNECTORS\90120-XX.PDF
R656 = RESISTOR: RES 1K 1/10W 1% 0402; Chkd/date: VASANTHA/281216; Crtd /date: MAZHAR/150506; Custom_Duty: 15%; Customs_HS_Code: 85332119; Distributor_name: DIGIKEY; Distributor_part_number: P1.00KLCT-ND; Footprint Path: Y:\MIS_DATABASE\Library\ALTIUM_TOOL\PCB_FOOTPRINTS\Altium_Footprint_Lib.PcbLib; Height: 0.40MM; Library Path: Y:\MIS_DATABASE\Library\ALTIUM_TOOL\SCHEMATICS_PARTS\MS_DISCRETE_Library.schlib; Mfr_name: PANASONIC-ECG; Mfr_part_number: ERJ-2RKF1001X; Mistral Part No: 110009030411-R; Package: 0402; Part_type: RESISTORS\FIXED; Project: VOCERA; RoHS: RoHS; Temperature: -55°C+155°C; Tolerance: 1%; Voltage: NA; Wattage: 1/10W; Weight: 0.8mg; Datasheet: Y:\MIS_DATABASE\DATASHEETS\RESISTORS\PAN-ERJSER_NOV17.PDF
TP118-TP121 = TESTPOINT: TESTPOINT CIR 20 SMD; Chkd/date: SHREESHAIL/171006; Crtd /date: MAZHAR/171006; Custom_Duty: NA; Customs_HS_Code: NA; Distributor_name: NA; Distributor_part_number: NA; Footprint Path: Y:\MIS_DATABASE\Library\ALTIUM_TOOL\PCB_FOOTPRINTS\Altium_Footprint_Lib.PcbLib; Height: NA; Library Path: Y:\MIS_DATABASE\Library\ALTIUM_TOOL\SCHEMATICS_PARTS\MS_DISCRETE_Library.schlib; MECHANICAL 3D STEP FILE: NA; Mfr_name: LOCAL; Mistral Part No: NA; Package: SMD; Project: BT MODULE_CSRBC04; RoHS: NA; Temperature: NA; Tolerance: NA; Voltage: NA; Wattage: NA; Weight: NA; Datasheet: NA
U60 = TXB0104RUTR_UQFN12: IC 4-BIT BIDIRECTIONAL VOLTAGE-LEVEL TRANSLATOR UQFN12; Chkd/date: MANIRAJA/281117; Crtd /date: ALVY/271117; Custom_Duty: 15%; Customs_HS_Code: 85423100; Distributor_name: DIGIKEY; Distributor_part_number: 296-25888-1-ND; Height: 0.55MM; Manufacturer: TEXAS INSTRUMENTS; Mistral Part No: 141017110007-R; Package: UQFN12; Part_type: ICS\INTERFACE\LEVEL TRANSLATOR; Project: RSAPR_TYPE-II_3U-SBC; RoHS: RoHS; Temperature: -40°C+85°C; Tolerance: NA; Voltage: NA; Wattage: NA; Weight: 4.70mg; Datasheet: Y:\MIS_DATABASE\DATASHEETS\ICS\INTERFACE\TXB0104.PDF
U65 = SN74CB3Q3257PWR_TSSOP16: IC 4BIT 1-OF-2 FET MULTIPLEXER/DEMULTIPLEXER TSSOP16; Chkd/date: SUHAS/251010; Crtd /date: USMAN/060109; Custom_Duty: 15%; Customs_HS_Code: 85423100; Distributor_name: DIGIKEY; Distributor_part_number: 296-19138-1-ND; Height: 1.20MM; Manufacturer: TEXAS INSTRUMENTS; Mistral Part No: 141009030117-R; Package: TSSOP16; Part_type: ICS\DIGITAL\COMBINATIONAL; Project: OMAP_EVM; RoHS: Sb/ Br FREE; Temperature: -40°C+85°C; Datasheet: Y:\MIS_DATABASE\DATASHEETS\ICS\DIGITAL\COMBINATIONAL\SN74CB3Q3257.PDF
U70 = TCA6424ARGJR_QFN32: IC I2C I/O EXPANDER 24B UQFN32; Chkd/date: NAVEED/100715; Crtd /date: NAVEED/100914; Custom_Duty: 15%; Customs_HS_Code: 85423100; Distributor_name: DIGIKEY; Distributor_part_number: 296-27844-1-ND; Height: 0.60MM; Mfr_name: TEXAS INSTRUMENTS; Mistral Part No: 141014090009-R; Package: UQFN32; Part_type: ICS\DIGITAL\BUSTRANSCEIVER; Project: ZK_BIOMETRIC; RoHS: RoHS; Temperature: -40°C+85°C; Weight: NA; Datasheet: Y:\MIS_DATABASE\DATASHEETS\ICS\DIGITAL\BUSTRANSCEIVER\TCA6424AR.PDF
U110 = TCA6408ARGTR_VQFN16: IC 8-BIT I2C AND SMBUS I/O EXPANDER WITH INTERRUPT O/P VQFN16; Chkd/date: MANIRAJA/151018; Crtd /date: MANIRAJA/151018; Custom_Duty: 15%; Customs_HS_Code: 85423100; Distributor_name: DIGIKEY; Distributor_part_number: 296-24825-1-ND; Footprint Path: Y:\MIS_DATABASE\Library\ALTIUM_TOOL\PCB_FOOTPRINTS\Altium_Footprint_Lib.PcbLib; Height: 1.00MM; Library Path: Y:\MIS_DATABASE\Library\ALTIUM_TOOL\SCHEMATICS_PARTS\MS_MISCINTERFACE_Library.schlib; Mfr_name: TEXAS INSTRUMENTS; Mistral Part No: 141018100011-R; Package: VQFN16; Part_type: ICS\INTERFACE; Project: TI_60GHz-AOP; RoHS: RoHS; Temperature: -40°C+85°C; Tolerance: NA; Voltage: NA; Wattage: NA; Weight: 24.1mg; Datasheet: Y:\MIS_DATABASE\DATASHEETS\ICS\INTERFACE\TCA6408AXX.PDF
U12 = AM62-EVM_BGA425: IC AM62 SoC MICROPROCESSOR BGA425; Chkd/date: ALVY/110621; Crtd /date: MANIRAJA/110621; Custom_Duty: 15%; Customs_HS_Code: 85423100; Distributor_name: NA; Distributor_part_number: NA; Footprint Path: Y:\MIS_DATABASE\Library\ALTIUM_TOOL\PCB_FOOTPRINTS\Altium_Footprint_Lib.PcbLib; Height: 0.65MM; Library Path: Y:\MIS_DATABASE\Library\ALTIUM_TOOL\SCHEMATICS_PARTS\MS_MICROPROCESSOR_Library.schlib; Mfr_name: TEXAS INSTRUMENTS; Mistral Part No: 141221060001; Package: BGA425; Part_type: ICS\DIGITAL\MICROPROCESSOR; Project: AM62_EVM_BRD; RoHS: NA; Temperature: NA; Tolerance: NA; Voltage: NA; Wattage: NA; Weight: NA; Datasheet: Y:\MIS_DATABASE\DATASHEETS\ICS\DIGITAL\MICROCONTROLLER\AM62-SoC_SVB.PDF

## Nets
DGND: C1.1 C8.1 C11.1 C43.2 C45.2 C115.2 C129.1 C355.2 C356.2 C371.2 C372.2 C385.1 C404.1 C408.1 C422.1 C496.1 C497.1 C509.2 D1.1(A) D14.1(A) FL21.2 J7.4(GND) J19.1A J19.4A J19.7A J19.10A J21.6 J21.7 J21.10 J21.13 J21.16 J21.19 J21.22 J21.25 J21.28 J21.31 J21.34 J21.37 J21.40 Q1.4(S1) Q1.7(S2) Q3.4(S1) Q3.7(S2) R16.1 R67.1 R68.2 R69.2 R94.1 R156.2 R199.1 R418.2 R431.1 R488.1 R647.2 R656.1 R657.1 R659.1 R714.1 U3.8(GND1) U3.9(GND2) U34.2(GND) U60.6(GND) U63.8(GND) U65.8(GND) U70.25(GND) U70.33(EP) U99.3(GND) U105.3(GND) U110.6(GND) U110.17(EP) ; also on sheet 1 10 11 12 13 14 15 16 17 18 19 20 21 22 23 24 25 26 27 28 29 30 31 32 33 34 35 40 41 42 43
VBUS_5V0_TYPEA1: C355.1 C371.1 J7.1(VCC) R649.2 U34.4(OUT)
VBUS_TYPEC2: R152.2 ; also on sheet 10 35
VCC_1V8: C8.2 C496.2 C509.1 R684.1 U3.16(VCCB) U60.1(VCCA) U105.5(VCC) ; also on sheet 12 13 14 18 19 21 25 34 40 42
VCC_3V3_SYS: C1.2 C11.2 C43.1 C45.1 C129.2 C385.2 C404.2 C408.2 C422.2 C497.2 FL10.2 J19.15A R17.2 R88.2 R165.1 R176.2 R187.2 R188.2 R193.2 R459.2 R475.1 R486.2 R650.1 R655.2 R658.2 R660.2 R713.2 U3.1(VCCA) U60.11(VCCB) U63.16(VCC) U65.16(VCC) U70.27(VCCP) U70.31(VCC) U99.5(VCC) U110.14(VCCP) U110.15(VCCI) ; also on sheet 10 12 13 14 18 19 20 22 23 24 25 26 27 29 30 31 32 33 34 35 40 41 42 43
VCC_5V0: C115.1 C356.1 U34.3(IN) ; also on sheet 10 11 33 41
ADDR_IO_EXP: R488.2 U70.26(ADDR)
ADDR_IO_EXP1: R714.2 U110.16(ADDR)
BT_UART_WAKE_SOC_3V3: U70.10(P11) ; also on sheet 18
CH1_LVDS_A0N: J21.11 U12.AA5(OLDI0_A0N)
CH1_LVDS_A0P: J21.12 U12.Y6(OLDI0_A0P)
CH1_LVDS_A1N: J21.14 U12.AD3(OLDI0_A1N)
CH1_LVDS_A1P: J21.15 U12.AB4(OLDI0_A1P)
CH1_LVDS_A2N: J21.20 U12.Y8(OLDI0_A2N)
CH1_LVDS_A2P: J21.21 U12.AA8(OLDI0_A2P)
CH1_LVDS_A3N: J21.23 U12.AB6(OLDI0_A3N)
CH1_LVDS_A3P: J21.24 U12.AA7(OLDI0_A3P)
CH1_LVDS_CLKN: J21.17 U12.AD4(OLDI0_CLK0N)
CH1_LVDS_CLKP: J21.18 U12.AE3(OLDI0_CLK0P)
CH2_LVDS_A0N: J21.26 U12.AC6(OLDI0_A4N)
CH2_LVDS_A0P: J21.27 U12.AC5(OLDI0_A4P)
CH2_LVDS_A1N: J21.29 U12.AE5(OLDI0_A5N)
CH2_LVDS_A1P: J21.30 U12.AD6(OLDI0_A5P)
CH2_LVDS_A2N: J21.35 U12.AE6(OLDI0_A6N)
CH2_LVDS_A2P: J21.36 U12.AD7(OLDI0_A6P)
CH2_LVDS_A3N: J21.38 U12.AD8(OLDI0_A7N)
CH2_LVDS_A3P: J21.39 U12.AE7(OLDI0_A7P)
CH2_LVDS_CLKN: J21.32 U12.AE4(OLDI0_CLK1N)
CH2_LVDS_CLKP: J21.33 U12.AD5(OLDI0_CLK1P)
CSI0_RXCLKN: J19.8A U12.AD15(CSI0_RXCLKN)
CSI0_RXCLKP: J19.9A U12.AE15(CSI0_RXCLKP)
CSI0_RXN0: J19.2A U12.AB14(CSI0_RXN0)
CSI0_RXN1: J19.5A U12.AD14(CSI0_RXN1)
CSI0_RXP0: J19.3A U12.AC15(CSI0_RXP0)
CSI0_RXP1: J19.6A U12.AE14(CSI0_RXP1)
CSI_GPIO1: J19.11A U70.14(P15)
CSI_GPIO2: J19.12A U70.15(P16)
CSI_I2C2_SCL: J19.13A ; also on sheet 33
CSI_I2C2_SDA: J19.14A ; also on sheet 33
EEPROM_VDD: FL10.1 J21.1
EXP_HAT_DETECT: R187.1 U70.8(P07) ; also on sheet 33
EXP_PS_3V3_EN: U70.6(P05) ; also on sheet 33
EXP_PS_5V0_EN: U70.7(P06) ; also on sheet 33
EXP_SPI2_CLK: U63.5(2B1) ; also on sheet 33
EXP_SPI2_CS0/EHRPWM0_A: U63.2(1B1) ; also on sheet 33
EXP_SPI2_D0: U63.11(3B1) ; also on sheet 33
EXP_SPI2_D1/ECAP2_IN_APWM_OUT: U63.14(4B1) ; also on sheet 33
GPIO1_23_INTn: R485.1 ; also on sheet 42 43
GPIO_AUD_RSTn: U110.4(P2) ; also on sheet 40
GPIO_CPSW1_RST: U70.2(P01) ; also on sheet 23
GPIO_CPSW2_RST: U70.1(P00) ; also on sheet 24
GPIO_eMMC_RSTn: U110.5(P3) ; also on sheet 19
GPIO_HDMI_RSTn: U70.13(P14) ; also on sheet 41
GPIO_TS_RSTn: R475.2 U105.1(A) U110.3(P1)
HDMI_INTn: U70.17(P20) ; also on sheet 41
IO_EXP1_INTn: R713.1 U110.11(~{INT})
IO_EXP_INTn: R485.2 R486.1 U70.32(~{INT})
IO_EXP_TEST_LED: R198.1 R199.2 U70.24(P27)
LVDS_SHIELD: FL21.1 J21.SH1 J21.SH2 J21.SH3 J21.SH4
MCASP1_ACLKX: U60.7(B4) U65.4(1A) ; also on sheet 32
MCASP1_ACLKX_AUD: U65.3(1B2) ; also on sheet 40
MCASP1_ACLKX_BT_1V8: U60.5(A4) ; also on sheet 18
MCASP1_ACLKX_HDMI: U65.2(1B1) ; also on sheet 41
MCASP1_AFSX: U60.8(B3) U65.7(2A) ; also on sheet 32
MCASP1_AFSX_AUD: U65.6(2B2) ; also on sheet 40
MCASP1_AFSX_BT_1V8: U60.4(A3) ; also on sheet 18
MCASP1_AFSX_HDMI: U65.5(2B1) ; also on sheet 41
MCASP1_AXR0: U60.9(B2) U65.9(3A) ; also on sheet 32
MCASP1_AXR0_AUD: U65.10(3B2) ; also on sheet 40
MCASP1_AXR0_BT_1V8: U60.3(A2) ; also on sheet 18
MCASP1_AXR0_HDMI: U65.11(3B1) ; also on sheet 41
MCASP1_AXR2: U60.10(B1) U65.12(4A) ; also on sheet 32
MCASP1_AXR2_AUD: U65.13(4B2) ; also on sheet 40
MCASP1_AXR2_BT_1V8: U60.2(A1) ; also on sheet 18
MCASP1_BUF_BT_EN: R657.2 R658.1 U60.12(OE) U70.20(P23)
MCASP1_FET_EN: R459.1 R659.2 U65.15(~{OE}) U70.19(P22)
MCASP1_FET_SEL: J24.1 R655.1 U65.1(S) U70.21(P24)
MMC1_SD_EN: U70.4(P03) ; also on sheet 20
OLDI_RESETn: J21.8 R684.2 U105.4(Y)
PD_I2C_IRQ: U70.18(P21) ; also on sheet 10
PRU_3V3_EN: U70.16(P17) ; also on sheet 32
PRU_DETECT: R193.1 U70.3(P02) ; also on sheet 32
RESETSTATz: U70.28(~{RESET}) U105.2(B) U110.1(~{RESET}) ; also on sheet 13 19 20 21 23 24 27 32 33 40 41 42
SOC_GPIO1_49: R94.2 R95.1 ; also on sheet 19
SoC_I2C0_SCL: J21.2 ; also on sheet 10 13 22 32 33 42
SoC_I2C0_SDA: J21.3 ; also on sheet 10 13 22 32 33 42
SOC_I2C1_SCL: U70.29(SCL) U110.12(SCL) ; also on sheet 14 22 26 40 41 42
SOC_I2C1_SDA: U70.30(SDA) U110.13(SDA) ; also on sheet 14 22 26 40 41 42
SOC_SPI2_CLK: U3.6(2A1) U63.7(2A) ; also on sheet 33
SOC_SPI2_CS0: U3.4(1A1) U63.4(1A) ; also on sheet 33
SOC_SPI2_D0: U3.5(1A2) U63.9(3A) ; also on sheet 33
SOC_SPI2_D1: U3.7(2A2) U63.12(4A) ; also on sheet 33
SOC_UART1_CTS: U63.10(3B2) ; also on sheet 31
SOC_UART1_CTS_BT_1V8: U3.12(1B2) ; also on sheet 18
SOC_UART1_RTS: U63.13(4B2) ; also on sheet 31
SOC_UART1_RTS_BT_1V8: U3.10(2B2) ; also on sheet 18
SOC_UART1_RX_BT_1V8: U3.13(1B1) ; also on sheet 18
SOC_UART1_RXD: U63.3(1B2) ; also on sheet 31
SOC_UART1_TX_BT_1V8: U3.11(2B1) ; also on sheet 18
SOC_UART1_TXD: U63.6(2B2) ; also on sheet 31
SoC_USB0_DM: U12.AE11(USB0_DM) ; also on sheet 35
SoC_USB0_DP: U12.AD11(USB0_DP) ; also on sheet 35
SoC_USB0_DRVVBUS: U12.C20(USB0_DRVVBUS) ; also on sheet 10
SoC_USB0_VBUS: R153.1 R156.1 U12.AC11(USB0_VBUS)
SoC_USB1_DM: L9.1(IN1) U12.AD10(USB1_DM)
SoC_USB1_DP: L9.4(OUT2) U12.AE9(USB1_DP)
SoC_USB1_DRVVBUS: R650.2 U12.F18(USB1_DRVVBUS) U34.1(EN)
SoC_USB1_VBUS: R647.1 R648.1 U12.AB10(USB1_VBUS)
TS_INT#: J21.9 R165.2 U70.23(P26)
UART1_FET_BUF_EN: R660.1 U3.14(~{2OE}) U3.15(~{1OE}) U70.11(P12) U99.2(A)
UART1_FET_BUF_EN_INV: U63.15(~{OE}) U99.4(Y)
UART1_FET_SEL: R176.1 R431.2 U63.1(S) U70.22(P25)
USB0_TYPEACONN1_DM: J7.2(D-) L9.2(IN2) U34.5(D1)
USB0_TYPEACONN1_DP: J7.3(D+) L9.3(OUT1) U34.6(D2)
USB_TYPEA_EARTH: C372.1 J7.SH1 J7.SH2 R418.1
VPP_LDO_EN: U70.5(P04) ; also on sheet 12
WL_LT_EN: U70.12(P13) ; also on sheet 18
WLAN_ALERT_3V3: U70.9(P10) ; also on sheet 18
WLAN_SDIO_RST_3V3: U110.2(P0) ; also on sheet 18
N16925380: R67.2 U12.AA14(CSI0_RXRCALIB)
N17726648: D1.3(C) R152.1 R153.2
N18904630: LD1.1(CATHODE) Q1.1(D1) Q1.2(D2) Q1.5(D3) Q1.6(D4) Q1.8(D5)
N18904632: Q1.3(G) R95.2
N18904656: LD1.2(ANODE) R88.1
N18904815: LD11.1(CATHODE) Q3.1(D1) Q3.2(D2) Q3.5(D3) Q3.6(D4) Q3.8(D5)
N18904817: Q3.3(G) R198.2
N18904841: LD11.2(ANODE) R188.1
N19880817: R68.1 U12.AC9(USB1_RCALIB)
N19880821: R69.1 U12.AE10(USB0_RCALIB)
N19885322: D14.3(C) R648.2 R649.1
N20066520: J24.2 R656.2
N20704463: R16.2 U3.2(1DIR)
N20704480: R17.1 U3.3(2DIR)
N20717871: TP118.1(TP) U110.7(P4)
N20717874: TP119.1(TP) U110.8(P5)
N20717877: TP120.1(TP) U110.9(P6)
N20717880: TP121.1(TP) U110.10(P7)

Not connected (* = marked no-connect by the designer): D1 2(NC)*; D14 2(NC)*; J19 1B* 2B* 3B* 4B* 5B* 6B* 7B* 8B* 9B* 10B* 11B* 12B* 13B* 14B* 15B*; J21 4* 5*; U12 AA12(RSVD6)* AB12(CSI0_RXN3)* AC13(CSI0_RXP3)* AD13(CSI0_RXN2)* AE13(CSI0_RXP2)* Y15(RSVD7)*; U65 14(4B1)*; U99 1(NC)*

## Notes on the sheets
sheet 36
- USB1 - USB 2.0 TYPE-A
- D-Note :-
  Use power switch with OC indication
  Example TPS2051
  Connect OC output of the power switch to SoC
  IO for USB VBUS over load detection
  Refer SK-AM62P-LP schematics
- R-Note
  Pullup is DNI
  USBx_DRVVBUS has internal
  pulldown enabled
- D-Note :-
  DNI USBx_DRVVBUS pullup and
  pulldown to implement wakeup
  from deep sleep.
  For Normal USB operation, there
  is an internal pulldown enabled
  during SOC reset
- 90E
- 90E
- DLW21SZ900HQ2B
- D-Note :-
  Provide provision to bypass the CMC using 0R resistor
  for performance testing
- Silk: TYPE-A
- D-Note:- VBUS connection is optional for Host configuration
- D-Note:- Refer USB VBUS Design Guidelines section of SoC data sheet
- D-Note:- Refer USB VBUS Design Guidelines section of SoC data sheet
sheet 37
- OLDI DISPLAY INTERFACE
- 100E
- 100E
- 100E
- OLDI RESET
- 100E
- 100E
- D-Note:-
  Add a series resistor to the GPIO
  input for isolation or testing
  Refer SK-AM62P-LP schematics
- 100E
- 100E
- 100E
- 100E
- 100E
- D-Note :-
  ANDing logic additionally performs level translation
  Verify the Reset IO level compatibility before
  optimizing the reset ANDing logic.
  IO level mismatch could cause supply leakage and
  affect SOC operation
- D-Note:-
  Add a cap after the ferrite
  to minimize resonance
- SoC UART1 FET SWITCH & BUFFER
- SoC_MAIN_UART1_RXD
- SoC_MAIN_UART1_CTS
- SoC_MAIN_UART1_TXD
- SoC_MAIN_UART1_RTS
- DIR=H : A ->B
  DIR=L : B ->A
- INPUT/OUTPUT
- OEn
- SEL
- An
- L
- H(DEFAULT)
- An=nB2
- FT4232
- L
- L
- An=nB1
- USER EXPANSION CONNECTOR
sheet 38
- CSI INTERFACE
- R-Note :-
  Based on End product requirement, interface
  the CSI signals to respective attach devices
- CSI CAMERA HEADER
- 100E
- 100E
- 100E
- Reserved Pins
- Silk: CSI
- USER TEST LEDS
- SoC GPIO
- IO EXP GPIO
sheet 39
- IO EXPANDERS
- I2C ADDRESS: 0x20
- I2C ADDRESS: 0x22
- MCASP1 FET SWITCH & BUFFER
- INPUT/OUTPUT
- OEn
- SEL
- An
- L
- H(DEFAULT)
- An=nB2
- MCASP1 - CODEC
- L
- L
- An=nB1
- MCASP1 - HDMI
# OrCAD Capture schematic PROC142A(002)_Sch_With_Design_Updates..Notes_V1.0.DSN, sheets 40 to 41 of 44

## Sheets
40 40. AUDIO CODEC: size C; title: AUDIO CODEC
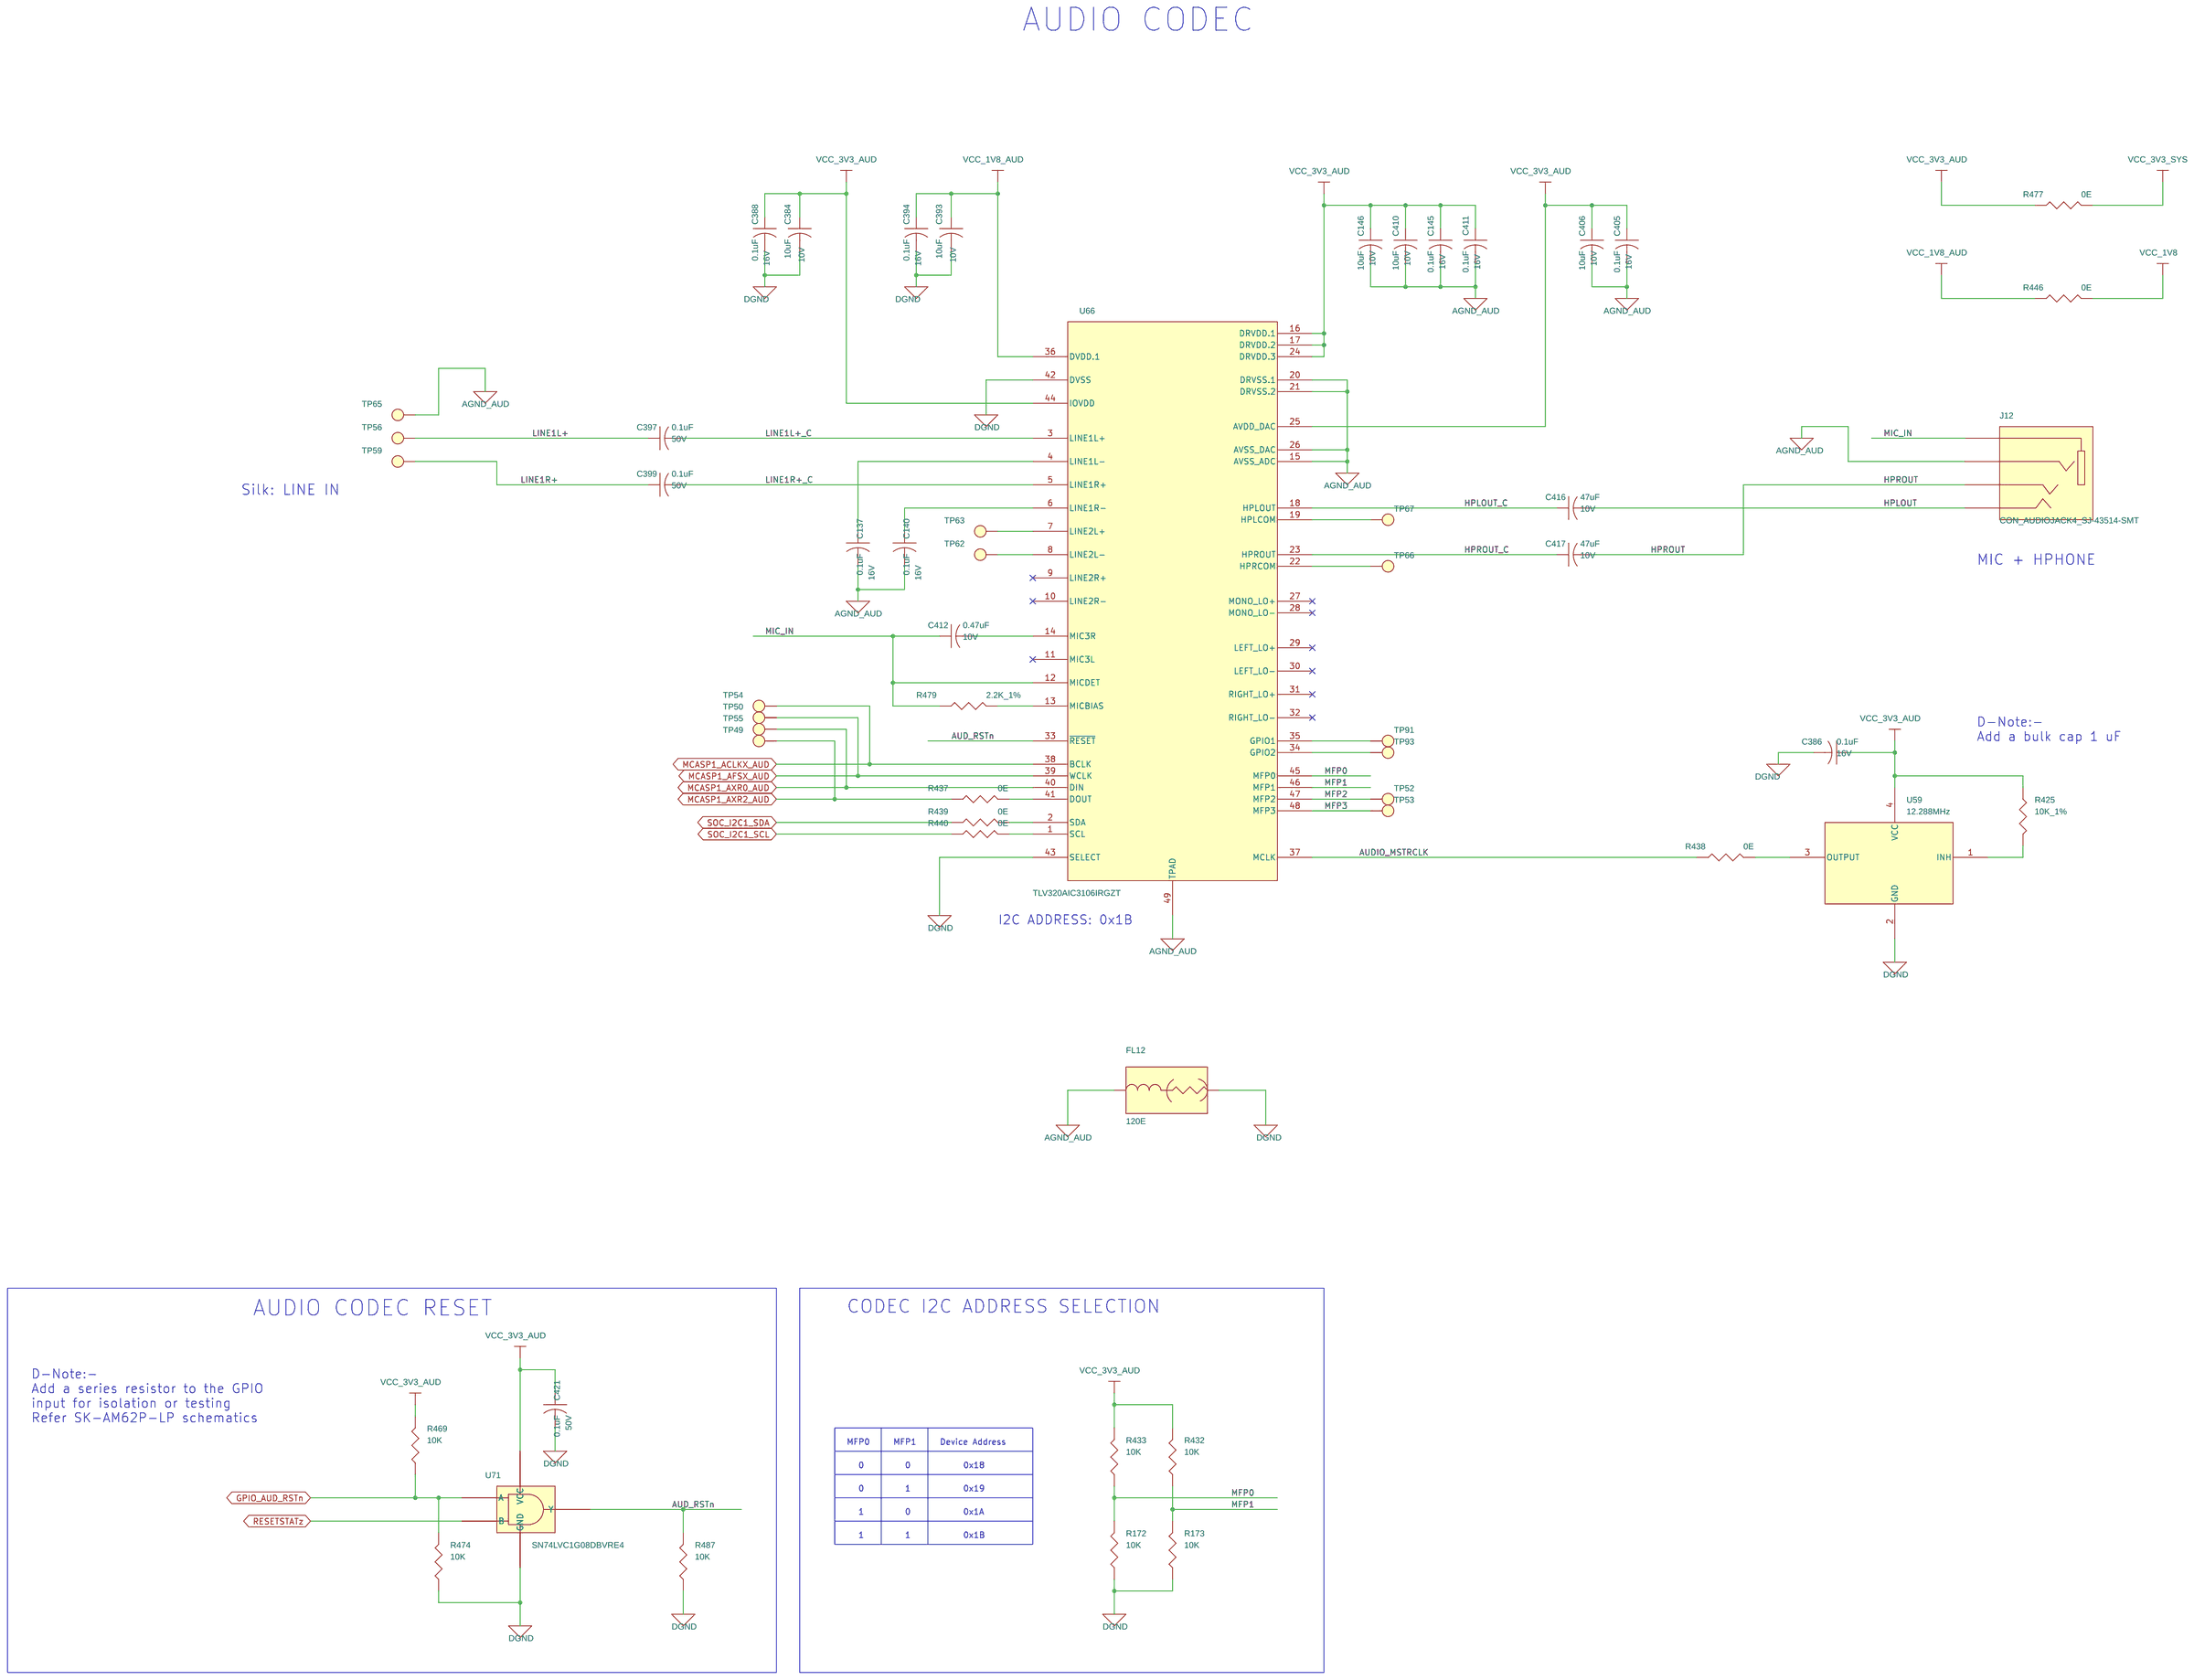
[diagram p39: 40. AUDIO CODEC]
41 41. HDMI INTERFACE: size C; title: HDMI INTERFACE

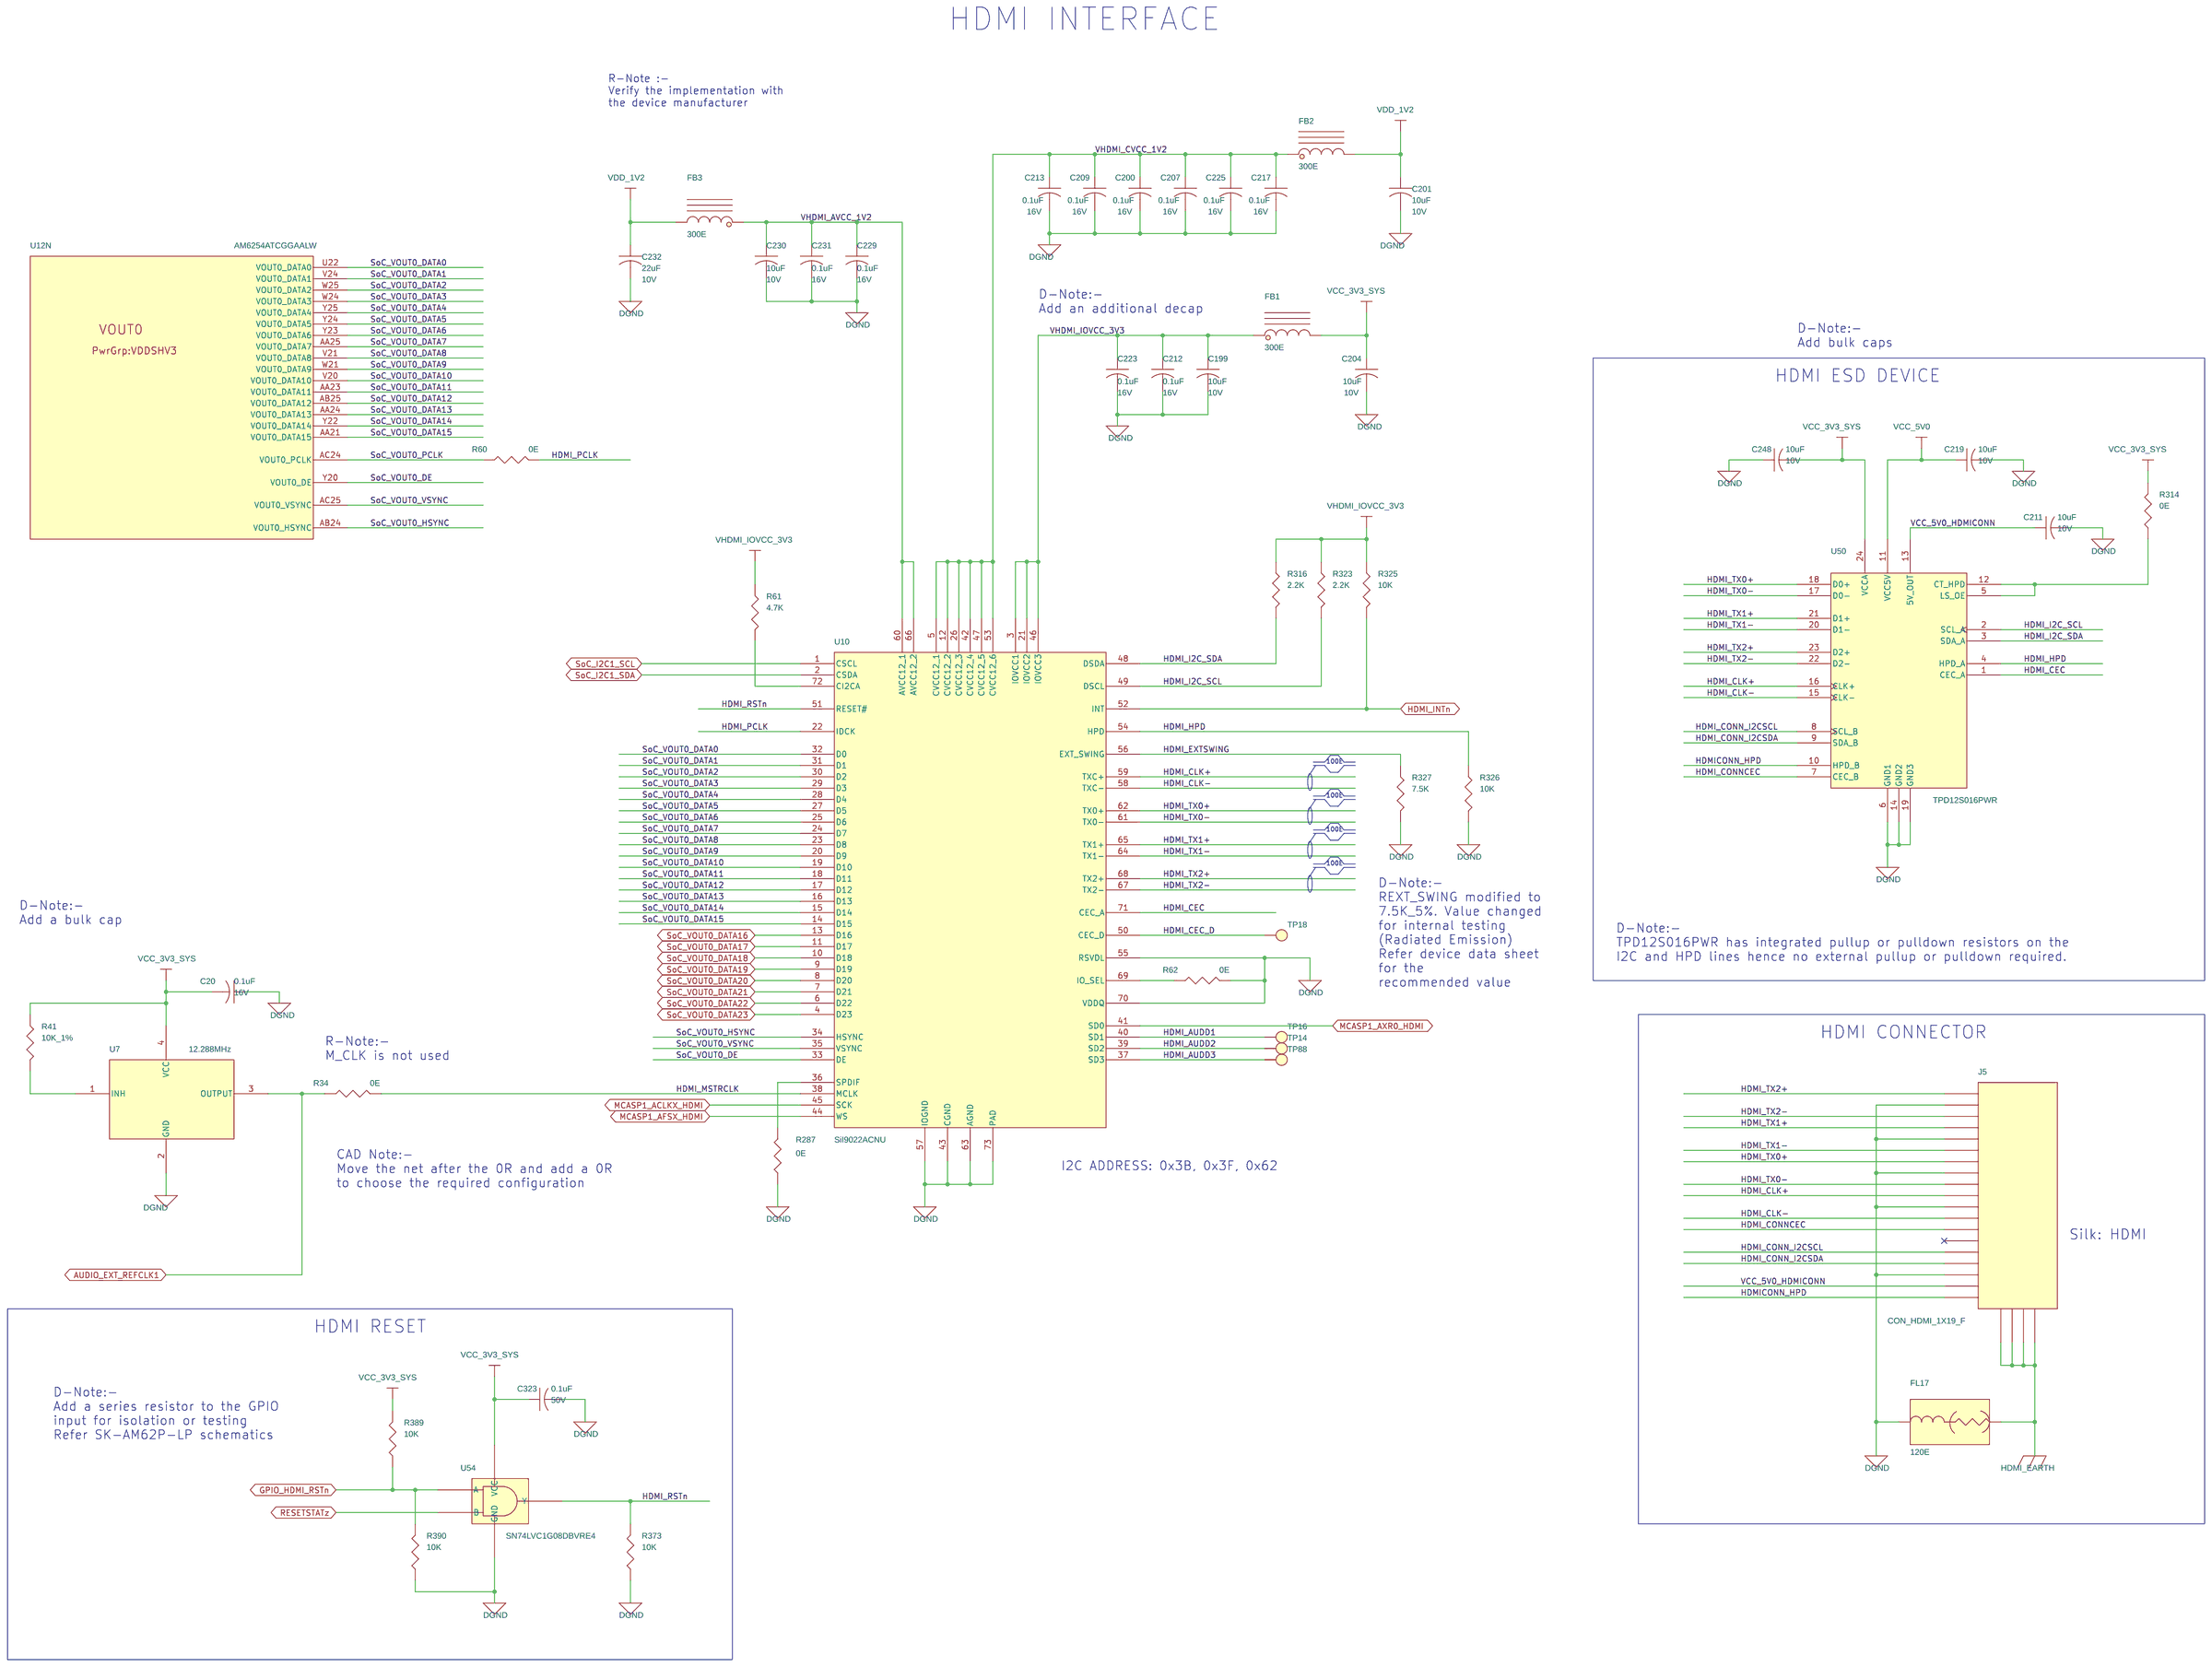
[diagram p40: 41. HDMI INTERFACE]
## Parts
sheet 40. AUDIO CODEC
C137  0.1uF  [CAP0201_0-5]
C140  0.1uF  [CAP0201_0-5]
C145  0.1uF  [CAP0201_0-5]
C146  10uF  [CAP0402_0-75]
C384  10uF  [CAP0402_0-75]
C386  0.1uF  [CAP0201_0-5]
C388  0.1uF  [CAP0201_0-5]
C393  10uF  [CAP0402_0-75]
C394  0.1uF  [CAP0201_0-5]
C397  0.1uF  [CAP0402_0-75]
C399  0.1uF  [CAP0402_0-75]
C405  0.1uF  [CAP0201_0-5]
C406  10uF  [CAP0402_0-75]
C410  10uF  [CAP0402_0-75]
C411  0.1uF  [CAP0201_0-5]
C412  0.47uF  [CAP0402_0-75]
C416  47uF  [CAP1206_2]
C417  47uF  [CAP1206_2]
C421  0.1uF  [CAP0402_0-75]
FL12  120E  [EMIFIL_BLM15A_0402_0-6]
J12  CON_AUDIOJACK4_SJ-43514-SMT  [CON_AV4_SJ-43514-SMT_S_R_S_5-1]
R172  10K  [RES0201_0-5]
R173  10K  [RES0201_0-5]
R425  10K_1%  [RES0201_0-5]
R432  10K  [RES0201_0-5]
R433  10K  [RES0201_0-5]
R437  0E  [RES0201_0-5]
R438  0E  [RES0201_0-5]
R439  0E  [RES0201_0-5]
R440  0E  [RES0201_0-5]
R446  0E  [RES0201_0-5]
R469  10K  [RES0201_0-5]
R474  10K  [RES0201_0-5]
R477  0E  [RES0201_0-5]
R479  2.2K_1%  [RES0201_0-5]
R487  10K  [RES0201_0-5]
TP49  TP20_SMD  [TP20_SMD]
TP50  TP20_SMD  [TP20_SMD]
TP52  TP20_SMD  [TP20_SMD]
TP53  TP20_SMD  [TP20_SMD]
TP54  TP20_SMD  [TP20_SMD]
TP55  TP20_SMD  [TP20_SMD]
TP56  THRU HOLE  [TP_40X65]
TP59  THRU HOLE  [TP_40X65]
TP62  TP20_SMD  [TP20_SMD]
TP63  TP20_SMD  [TP20_SMD]
TP65  THRU HOLE  [TP_40X65]
TP66  TP20_SMD  [TP20_SMD]
TP67  TP20_SMD  [TP20_SMD]
TP91  TP20_SMD  [TP20_SMD]
TP93  TP20_SMD  [TP20_SMD]
U59  12.288MHz  [OSC4_KC2520B_100X80_SMD_0-8]
U66  TLV320AIC3106IRGZT  [VQFN48_19-68_285X285]
U71  SN74LVC1G08DBVRE4  [SOT23-5]
sheet 41. HDMI INTERFACE
C20  0.1uF  [CAP0201_0-5]
C199  10uF  [CAP0402_0-75]
C200  0.1uF  [CAP0201_0-5]
C201  10uF  [CAP0402_0-75]
C204  10uF  [CAP0402_0-75]
C207  0.1uF  [CAP0201_0-5]
C209  0.1uF  [CAP0201_0-5]
C211  10uF  [CAP0402_0-75]
C212  0.1uF  [CAP0201_0-5]
C213  0.1uF  [CAP0201_0-5]
C217  0.1uF  [CAP0201_0-5]
C219  10uF  [CAP0402_0-75]
C223  0.1uF  [CAP0201_0-5]
C225  0.1uF  [CAP0201_0-5]
C229  0.1uF  [CAP0201_0-5]
C230  10uF  [CAP0402_0-75]
C231  0.1uF  [CAP0201_0-5]
C232  22uF  [CAP0603_1]
C248  10uF  [CAP0402_0-75]
C323  0.1uF  [CAP0402_0-75]
FB1  300E  [IND0603]
FB2  300E  [IND0603]
FB3  300E  [IND0603]
FL17  120E  [EMIFIL_BLM15A_0402_0-6]
J5  CON_HDMI_1X19_F  [CON_19X1_10029449-001RLF_S_R_S_6-3]
R34  0E  [RES0201_0-5]
R41  10K_1%  [RES0201_0-5]
R60  0E  [RES0201_0-5]
R61  4.7K  [RES0201_0-5]
R62  0E  [RES0201_0-5]
R287  0E  [RES0201_0-5]
R314  0E  [RES0201_0-5]
R316  2.2K  [RES0402_0-5]
R323  2.2K  [RES0402_0-5]
R325  10K  [RES0201_0-5]
R326  10K  [RES0402_0-5]
R327  7.5K  [RES0402_0-5]
R373  10K  [RES0201_0-5]
R389  10K  [RES0201_0-5]
R390  10K  [RES0201_0-5]
TP14  TP20_SMD  [TP20_SMD]
TP16  TP20_SMD  [TP20_SMD]
TP18  TP20_SMD  [TP20_SMD]
TP88  TP20_SMD  [TP20_SMD]
U7  12.288MHz  [OSC4_KC2520B_100X80_SMD_0-8]
U10  SiI9022ACNU  [QFN72_19-68_390X390_0-9]
U50  TPD12S016PWR  [TSSOP24_25-59_315X180_1-2]
U54  SN74LVC1G08DBVRE4  [SOT23-5]
sheet 42. OSCILLATOR
U12  AM6254ATCGGAALW  [BGA425_19-68_510X510_0-7]  (sections A,B,C,D,E,F,G,H,I,J,K,L,M,N,O,P,Q,R)

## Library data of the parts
C137 C140 C145 C200 C207 C209 C212 C213 C217 C223 C225 C229 C231 C386 C388 C394 C405 C411 = CAP: CAP CERAMIC 0.1uF 16V 10% X5R 0201; Chkd/date: MANIRAJA/230118; Crtd /date: MANIRAJA/230118; Custom_Duty: 15%; Customs_HS_Code: 85322990; Distributor_name: DIGIKEY; Distributor_part_number: 490-14305-1-ND; Footprint Path: Y:\MIS_DATABASE\Library\ALTIUM_TOOL\PCB_FOOTPRINTS\Altium_Footprint_Lib.PcbLib; Height: 0.33MM; Library Path: Y:\MIS_DATABASE\Library\ALTIUM_TOOL\SCHEMATICS_PARTS\MS_DISCRETE_Library.schlib; Mfr_name: MURATA; Mfr_part_number: GRM033R61C104KE14D; Mistral Part No: 120009030072-R; Package: 0201; Part_type: CAPACITORS\CERAMIC; Project: TI_MAXIE_CPB; RoHS: RoHS; Temperature: -55°C+85°C; Tolerance: 10%; Voltage: 16V; Wattage: NA; Weight: 0.33mg; Datasheet: Y:\MIS_DATABASE\DATASHEETS\CAPACITORS\GRM033R61C104KE14.PDF
C146 C199 C201 C204 C211 C219 C230 C248 C384 C393 C406 C410 = CAP: CAP CERAMIC 10uF 10V 20% X5R 0402; Chkd/date: MANIRAJA/300520; Crtd /date: ALVY/260520; Custom_Duty: 15%; Customs_HS_Code: 85322990; Distributor_name: DIGIKEY; Distributor_part_number: 490-GRM155R61A106ME11DTR-ND; Footprint Path: Y:\MIS_DATABASE\Library\ALTIUM_TOOL\PCB_FOOTPRINTS\Altium_Footprint_Lib.PcbLib; Height: 0.55MM; Library Path: Y:\MIS_DATABASE\Library\ALTIUM_TOOL\SCHEMATICS_PARTS\MS_DISCRETE_Library.schlib; Mfr_name: MURATA; Mfr_part_number: GRM155R61A106ME11D; Mistral Part No: 120013110019-R; Package: 0402; Part_type: CAPACITORS\CERAMIC; Project: QCS610_NANOSOM; RoHS: RoHS; Temperature: -55°C+85°C; Tolerance: 20%; Voltage: 10V; Wattage: NA; Weight: 3.1mg; Datasheet: Y:\MIS_DATABASE\DATASHEETS\CAPACITORS\MURATA-GXX-SER_NOV17.PDF
C397 C399 C421 = CAP: CAP CERAMIC 0.1uF 50V 10% X7R 0402; Chkd/date: MANIRAJA/261020; Crtd /date: ALVY/211020; Custom_Duty: 15%; Customs_HS_Code: 85322990; Distributor_name: DIGIKEY; Distributor_part_number: 490-10700-1-ND; Footprint Path: Y:\MIS_DATABASE\Library\ALTIUM_TOOL\PCB_FOOTPRINTS\Altium_Footprint_Lib.PcbLib; Height: 0.55MM; Library Path: Y:\MIS_DATABASE\Library\ALTIUM_TOOL\SCHEMATICS_PARTS\MS_DISCRETE_Library.schlib; Mfr_name: MURATA; Mfr_part_number: GRM155R71H104KE14D; Mistral Part No: 120011100014-R; Package: 0402; Part_type: CAPACITORS\CERAMIC; Project: J7_CP; RoHS: RoHS; Temperature: -55°C+125°C; Tolerance: 10%; Voltage: 50V; Wattage: NA; Weight: 3.1mg; Datasheet: Y:\MIS_DATABASE\DATASHEETS\CAPACITORS\GRM155R71H104KE14.PDF
C412 = CAP: CAP CERAMIC 0.47uF 10V 10% X7R 0402; Chkd/date: MANIRAJA/310821; Crtd /date: ALVY/310821; Custom_Duty: 15%; Customs_HS_Code: 85322990; Distributor_name: DIGIKEY; Distributor_part_number: 490-14366-1-ND; Footprint Path: Y:\MIS_DATABASE\Library\ALTIUM_TOOL\PCB_FOOTPRINTS\Altium_Footprint_Lib.PcbLib; Height: 0.55MM; Library Path: Y:\MIS_DATABASE\Library\ALTIUM_TOOL\SCHEMATICS_PARTS\MS_DISCRETE_Library.schlib; Mfr_name: MURATA; Mfr_part_number: GRM155R71A474KE01D; Mistral Part No: 120021060019-R; Package: 0402; Part_type: CAPACITORS\CERAMIC; Project: TI_AM335x SK_BRD; RoHS: RoHS; Temperature: -55°C+125°C; Tolerance: 10%; Voltage: 10V; Wattage: NA; Weight: 1.5mg; Datasheet: Y:\MIS_DATABASE\DATASHEETS\CAPACITORS\GRM155R71A474KE01.PDF
C416 C417 = CAP: CAP CERAMIC 47uF 10V 20% X5R 1206; Chkd/date: USMAN/121213; Crtd /date: USMAN/121213; Custom_Duty: 15%; Customs_HS_Code: 85322990; Distributor_name: DIGIKEY; Distributor_part_number: 490-5528-1-ND; Footprint Path: Y:\MIS_DATABASE\Library\ALTIUM_TOOL\PCB_FOOTPRINTS\Altium_Footprint_Lib.PcbLib; Height: 1.80MM; Library Path: Y:\MIS_DATABASE\Library\ALTIUM_TOOL\SCHEMATICS_PARTS\MS_DISCRETE_Library.schlib; Mfr_name: MURATA; Mfr_part_number: GRM31CR61A476ME15L; Mistral Part No: 120013120015-R; Package: 1206; Part_type: CAPACITORS\CERAMIC; Project: DMP; RoHS: RoHS; Temperature: -55°C+85°C; Tolerance: 20%; Voltage: 10V; Wattage: NA; Weight: 40mg; Datasheet: Y:\MIS_DATABASE\DATASHEETS\CAPACITORS\MURATA-GXX-SER_NOV17.PDF
FL12 FL17 = EMIFILTER_IND: IND FERRITE BEAD CHIP 120E 2A 0402; Chkd/date: NAVEED/241114; Crtd /date: USMAN/170613; Custom_Duty: 24%; Customs_HS_Code: 85369090; Distributor_name: DIGIKEY; Distributor_part_number: 490-9656-1-ND; Footprint Path: Y:\MIS_DATABASE\Library\ALTIUM_TOOL\PCB_FOOTPRINTS\Altium_Footprint_Lib.PcbLib; Height: 0.55MM; Library Path: Y:\MIS_DATABASE\Library\ALTIUM_TOOL\SCHEMATICS_PARTS\MS_FILTER_Library.schlib; Mfr_name: MURATA; Mfr_part_number: BLM15PX121SN1D; Mistral Part No: 130013060022-R; Package: 0402; Part_type: INDUCTOR; Project: GEN_3-8; RoHS: RoHS; Temperature: -55°C+125°C; Tolerance: 25%; Voltage: NA; Wattage: NA; Weight: 1mg; Datasheet: Y:\MIS_DATABASE\DATASHEETS\DISCRETES\INDUCTORS\BLM15-SN1-SER.PDF
J12 = CON_AUDIOJACK4_SJ-43514-SMT: CON AUDIO JACK 4POS FEMALE RT SMD; Chkd/date: MAZHAR/230211; Crtd /date: MUDDU/300610; Custom_Duty: 24%; Customs_HS_Code: 85369090; Distributor_name: DIGIKEY; Distributor_part_number: CP-43514SJCT-ND; Footprint Path: Y:\MIS_DATABASE\Library\ALTIUM_TOOL\PCB_FOOTPRINTS\Altium_Footprint_Lib.PcbLib; Height: 5.10MM; Library Path: Y:\MIS_DATABASE\Library\ALTIUM_TOOL\SCHEMATICS_PARTS\MS_CONNECTOR_Library.schlib; Mfr_name: CUI INC; Mfr_part_number: SJ-43514-SMT-TR; Mistral Part No: 150010060028-R; Package: SMD; Part_type: CONNECTOR\JACK; Project: PB_BUGBASE; RoHS: RoHS; Temperature: -25°C+85°C; Tolerance: NA; Voltage: NA; Wattage: NA; Weight: 1100mg; Datasheet: Y:\MIS_DATABASE\DATASHEETS\CONNECTORS\SJ-4351X-SMT.PDF
R172 R173 R325 R373 R389 R390 R432 R433 R469 R474 R487 = RESISTOR: RES 10K 1/20W 5% 0201; Chkd/date: MANIRAJA/050517; Crtd /date: MANIRAJA/050517; Custom_Duty: 15%; Customs_HS_Code: 85332119; Distributor_name: DIGIKEY; Distributor_part_number: 311-10KNCT-ND; Footprint Path: Y:\MIS_DATABASE\Library\ALTIUM_TOOL\PCB_FOOTPRINTS\Altium_Footprint_Lib.PcbLib; Height: 0.26MM; Library Path: Y:\MIS_DATABASE\Library\ALTIUM_TOOL\SCHEMATICS_PARTS\MS_DISCRETE_Library.schlib; Mfr_name: YAGEO AMERICA; Mfr_part_number: RC0201JR-0710KL; Mistral Part No: 110010070051-R; Package: 0201; Part_type: RESISTORS\FIXED; Project: GOLDEN-I LITE; RoHS: RoHS; Temperature: -55°C+125°C; Tolerance: 5%; Voltage: NA; Wattage: 1/20W; Weight: 0.17mg; Datasheet: Y:\MIS_DATABASE\DATASHEETS\RESISTORS\RCXXXXL-SER_MAR18.PDF
R41 R425 = RESISTOR: RES 10K 1/20W 1% 0201; Chkd/date: VASANTHA/270117; Crtd /date: MANIRAJA/270117; Custom_Duty: 15%; Customs_HS_Code: 85332119; Distributor_name: DIGIKEY; Distributor_part_number: 311-10.0KMCT-ND; Footprint Path: Y:\MIS_DATABASE\Library\ALTIUM_TOOL\PCB_FOOTPRINTS\Altium_Footprint_Lib.PcbLib; Height: 0.26MM; Library Path: Y:\MIS_DATABASE\Library\ALTIUM_TOOL\SCHEMATICS_PARTS\MS_DISCRETE_Library.schlib; Mfr_name: YAGEO AMERICA; Mfr_part_number: RC0201FR-0710KL; Mistral Part No: 110011040018-R; Package: 0201; Part_type: RESISTORS\FIXED; Project: GOLDEN-I LITE; RoHS: RoHS; Temperature: -55°C+125°C; Tolerance: 1%; Voltage: NA; Wattage: 1/20W; Weight: 0.17mg; Datasheet: Y:\MIS_DATABASE\DATASHEETS\RESISTORS\RCXXXXL-SER_MAR18.PDF
R60 R437 = RESISTOR: RES 0E 1/20W 5% 0201; Chkd/date: NAVEED/301214; Crtd /date: MUDDU/120710; Custom_Duty: 15%; Customs_HS_Code: 85332119; Distributor_name: DIGIKEY; Distributor_part_number: 311-0.0NCT-ND; Footprint Path: Y:\MIS_DATABASE\Library\ALTIUM_TOOL\PCB_FOOTPRINTS\Altium_Footprint_Lib.PcbLib; Height: 0.26MM; Library Path: Y:\MIS_DATABASE\Library\ALTIUM_TOOL\SCHEMATICS_PARTS\MS_DISCRETE_Library.schlib; Mfr_name: YAGEO AMERICA; Mfr_part_number: RC0201JR-070RL; Mistral Part No: 110010070067-R; Package: 0201; Part_type: RESISTORS\FIXED; Project: PB_BUGBASE; RoHS: RoHS; SIGNAL_MODEL: RESISTOR_RES0201_0-5_0E_0E; Temperature: -55°C+125°C; Tolerance: 5%; Voltage: NA; Wattage: 1/20W; Weight: 0.17mg; Datasheet: Y:\MIS_DATABASE\DATASHEETS\RESISTORS\RCXXXXL-SER_MAR18.PDF
R34 R62 R287 R314 R438-R440 R446 R477 = RESISTOR: RES 0E 1/20W 5% 0201; Chkd/date: NAVEED/301214; Crtd /date: MUDDU/120710; Custom_Duty: 15%; Customs_HS_Code: 85332119; Distributor_name: DIGIKEY; Distributor_part_number: 311-0.0NCT-ND; Footprint Path: Y:\MIS_DATABASE\Library\ALTIUM_TOOL\PCB_FOOTPRINTS\Altium_Footprint_Lib.PcbLib; Height: 0.26MM; Library Path: Y:\MIS_DATABASE\Library\ALTIUM_TOOL\SCHEMATICS_PARTS\MS_DISCRETE_Library.schlib; Mfr_name: YAGEO AMERICA; Mfr_part_number: RC0201JR-070RL; Mistral Part No: 110010070067-R; Package: 0201; Part_type: RESISTORS\FIXED; Project: PB_BUGBASE; RoHS: RoHS; Temperature: -55°C+125°C; Tolerance: 5%; Voltage: NA; Wattage: 1/20W; Weight: 0.17mg; Datasheet: Y:\MIS_DATABASE\DATASHEETS\RESISTORS\RCXXXXL-SER_MAR18.PDF
R479 = RESISTOR: RES 2.2K 1/20W 1% 0201; Chkd/date: VASANTHA/270117; Crtd /date: MANIRAJA/270117; Custom_Duty: 15%; Customs_HS_Code: 85332119; Distributor_name: DIGIKEY; Distributor_part_number: YAG2572CT-ND; Footprint Path: Y:\MIS_DATABASE\Library\ALTIUM_TOOL\PCB_FOOTPRINTS\Altium_Footprint_Lib.PcbLib; Height: 0.26MM; Library Path: Y:\MIS_DATABASE\Library\ALTIUM_TOOL\SCHEMATICS_PARTS\MS_DISCRETE_Library.schlib; Mfr_name: YAGEO AMERICA; Mfr_part_number: RC0201FR-072K2L; Mistral Part No: 110017010016-R; Package: 0201; Part_type: RESISTORS\FIXED; Project: GOLDEN-I LITE; RoHS: RoHS; Temperature: -55°C+125°C; Tolerance: 1%; Voltage: NA; Wattage: 1/20W; Weight: 0.17mg; Datasheet: Y:\MIS_DATABASE\DATASHEETS\RESISTORS\RCXXXXL-SER_MAR18.PDF
TP14 TP16 TP18 TP49 TP50 TP52-TP55 TP62 TP63 TP66 TP67 TP88 TP91 TP93 = TESTPOINT: TESTPOINT CIR 20 SMD; Chkd/date: SHREESHAIL/171006; Crtd /date: MAZHAR/171006; Custom_Duty: NA; Customs_HS_Code: NA; Distributor_name: NA; Distributor_part_number: NA; Footprint Path: Y:\MIS_DATABASE\Library\ALTIUM_TOOL\PCB_FOOTPRINTS\Altium_Footprint_Lib.PcbLib; Height: NA; Library Path: Y:\MIS_DATABASE\Library\ALTIUM_TOOL\SCHEMATICS_PARTS\MS_DISCRETE_Library.schlib; MECHANICAL 3D STEP FILE: NA; Mfr_name: LOCAL; Mistral Part No: NA; Package: SMD; Project: BT MODULE_CSRBC04; RoHS: NA; Temperature: NA; Tolerance: NA; Voltage: NA; Wattage: NA; Weight: NA; Datasheet: NA
TP56 TP59 TP65 = TESTPOINT: TESTPOINT 1.0MM DRILL PTH; Chkd/date: MAZHAR/271211; Crtd /date: SHREESHAIL/041005; Distributor_name: NA; Distributor_part_number: NA; Height: NA; Mfr_name: LOCAL; Mistral Part No: 130009030938; Package: THRU-HOLE; Project: HSE; Datasheet: NA
U7 U59 = OSC_KC2016K: OSC 12.288MHz CMOS SMD; Chkd/date: MANIRAJA/061021; Crtd /date: ALVY/061021; Custom_Duty: 24%; Customs_HS_Code: 85437099; Distributor_name: DIGIKEY; Distributor_part_number: 1253-KC2520Z12.2880C1KX00CT-ND; Footprint Path: Y:\MIS_DATABASE\Library\ALTIUM_TOOL\PCB_FOOTPRINTS\Altium_Footprint_Lib.PcbLib; Height: 0.80MM; Library Path: Y:\MIS_DATABASE\Library\ALTIUM_TOOL\SCHEMATICS_PARTS\MS_DISCRETE_Library.schlib; Mfr_name: KYOCERA; Mfr_part_number: KC2520Z12.2880C1KX00; Mistral Part No: 130021100008-R; Package: SMD; Part_type: OSCILLATORS; Project: TI_AM62x SKEVM_BRD; RoHS: RoHS; Temperature: -40°C+85°C; Tolerance: NA; Voltage: NA; Wattage: NA; Weight: NA; Datasheet: Y:\MIS_DATABASE\DATASHEETS\MISC\CRY_OSC\KC-Z-SERPDF
U66 = TLV320AIC3106IRGZT_VQFN48: IC LOW-POWER STEREO AUDIO CODEC VQFN48; Chkd/date: SUHAS/261010; Crtd /date: MUDDU/150610; Custom_Duty: 15%; Customs_HS_Code: 85423100; Distributor_name: DIGIKEY; Distributor_part_number: TLV320AIC3106IRGZT-ND; Height: 1.00MM; Mfr_name: TEXAS INSTRUMENTS; Mistral Part No: 143010060003-R; Package: VQFN48; Part_type: ICS\TELECOM\CODEC; Project: CENTAURUS; RoHS: Sb/ Br FREE; Temperature: -40°C+85°C; Weight: NA; Datasheet: Y:\MIS_DATABASE\DATASHEETS\ICS\TELECOM\TLV320AIC3106IRGZT.PDF
U54 U71 = SN74LVC1G08DBVRE4_SOT23-5: IC SINGLE 2-INPUT POSITIVE AND GATE SOT23-5; Chkd/date: SUHAS/221010; Crtd /date: USMAN/151008; Custom_Duty: 15%; Customs_HS_Code: 85423100; Distributor_name: DIGIKEY; Distributor_part_number: SN74LVC1G08DBVRE4-ND; Height: 1.45MM; Mfr_name: TEXAS INSTRUMENTS; Mistral Part No: 141009060026-R; Part_type: ICS\DIGITAL\GATES; Project: KHAN_MAIN; RoHS: Sb/ Br FREE; Temperature: -40°C+85°C; Datasheet: Y:\MIS_DATABASE\DATASHEETS\ICS\DIGITAL\GATES\SN74LVC1G08.PDF
C20 = CAP: CAP CERAMIC 0.1uF 16V 10% X5R 0201; Alt_Mfr_name: YAGEO AMERICA; Alt_Mfr_part_number: CC0402KRX5R8BB104; Chkd/date: MANIRAJA/230118; Crtd /date: MANIRAJA/230118; Custom_Duty: 15%; Customs_HS_Code: 85322990; Distributor_name: DIGIKEY; Distributor_part_number: 490-14305-1-ND; Footprint Path: Y:\MIS_DATABASE\Library\ALTIUM_TOOL\PCB_FOOTPRINTS\Altium_Footprint_Lib.PcbLib; Height: 0.33MM; Library Path: Y:\MIS_DATABASE\Library\ALTIUM_TOOL\SCHEMATICS_PARTS\MS_DISCRETE_Library.schlib; Mfr_name: MURATA; Mfr_part_number: GRM033R61C104KE14D; Mistral Part No: 120009030072-R; Package: 0201; Part_type: CAPACITORS\CERAMIC; Project: TI_MAXIE_CPB; RoHS: RoHS; Temperature: -55°C+85°C; Tolerance: 10%; Voltage: 16V; Wattage: NA; Weight: 0.33mg; Datasheet: Y:\MIS_DATABASE\DATASHEETS\CAPACITORS\GRM033R61C104KE14.PDF
C232 = CAP: CAP CERAMIC 22uF 10V 20% X5R 0603; Chkd/date: MANIRAJA/230118; Crtd /date: MANIRAJA/230118; Custom_Duty: 15%; Customs_HS_Code: 85322990; Distributor_name: DIGIKEY; Distributor_part_number: 490-10476-1-ND; Footprint Path: Y:\MIS_DATABASE\Library\ALTIUM_TOOL\PCB_FOOTPRINTS\Altium_Footprint_Lib.PcbLib; Height: 1.00MM; Library Path: Y:\MIS_DATABASE\Library\ALTIUM_TOOL\SCHEMATICS_PARTS\MS_DISCRETE_Library.schlib; Mfr_name: MURATA; Mfr_part_number: GRM188R61A226ME15D; Mistral Part No: 120014100009-R; Package: 0603; Part_type: CAPACITORS\CERAMIC; Project: TI_MAXIE_CPB; RoHS: RoHS; Temperature: -55°C+85°C; Tolerance: 20%; Voltage: 10V; Wattage: NA; Weight: 6.3mg; Datasheet: Y:\MIS_DATABASE\DATASHEETS\CAPACITORS\GRM188R61A226ME15.PDF
C323 = CAP: CAP CERAMIC 0.1uF 50V 10% X7R 0402; Alt_Mfr_name: YAGEO AMERICA; Alt_Mfr_part_number: CC0402KRX5R8BB104; Chkd/date: MANIRAJA/261020; Crtd /date: ALVY/211020; Custom_Duty: 15%; Customs_HS_Code: 85322990; Distributor_name: DIGIKEY; Distributor_part_number: 490-10700-1-ND; Footprint Path: Y:\MIS_DATABASE\Library\ALTIUM_TOOL\PCB_FOOTPRINTS\Altium_Footprint_Lib.PcbLib; Height: 0.55MM; Library Path: Y:\MIS_DATABASE\Library\ALTIUM_TOOL\SCHEMATICS_PARTS\MS_DISCRETE_Library.schlib; Mfr_name: MURATA; Mfr_part_number: GRM155R71H104KE14D; Mistral Part No: 120011100014-R; Package: 0402; Part_type: CAPACITORS\CERAMIC; Project: J7_CP; RoHS: RoHS; Temperature: -55°C+125°C; Tolerance: 10%; Voltage: 50V; Wattage: NA; Weight: 3.1mg; Datasheet: Y:\MIS_DATABASE\DATASHEETS\CAPACITORS\GRM155R71H104KE14.PDF
FB1-FB3 = INDUCTOR_FERRITE: IND FERRITE CHIP 300E 500mA 0603; Alternate_mfr_name_A: TDK CORPORATION; Alternate_mfr_part_number_A: MMZ1608R301ATA00; Chkd/date: VASANTHA/190614; Crtd /date: NAVEED/160614; Custom_Duty: 24%; Customs_HS_Code: 85437099; Distributor_name: DIGIKEY; Distributor_name_A: DIGIKEY; Distributor_part_number: 445-2171-1-ND; Distributor_part_number_A: 445-2171-1-ND; Height: 0.75MM; Mfr_name: TDK CORPORATION; Mfr_part_number: MMZ1608R301A; Mistral Part No: 130014060028-R; Package: 0603; Part_type: INDUCTOR; Project: AEGIS_POM; RoHS: RoHS; Temperature: -55°C+125°C; Tolerance: NA; Voltage: NA; Wattage: NA; Weight: NA; Datasheet: Y:\MIS_DATABASE\DATASHEETS\DISCRETES\INDUCTORS\MMZSER.PDF
J5 = CON_HDMI_19X1: CON HDMI-A TYPE 1X19 0.50MM PITCH FEMALE RT SMD; Chkd/date: VASANTHA/060117; Crtd /date: MUDDU/060510; Custom_Duty: 24%; Customs_HS_Code: 85369090; Distributor_name: DIGIKEY; Distributor_part_number: 609-1010-1-ND; Footprint Path: Y:\MIS_DATABASE\Library\ALTIUM_TOOL\PCB_FOOTPRINTS\Altium_Footprint_Lib.PcbLib; Height: 6.30MM; Library Path: Y:\MIS_DATABASE\Library\ALTIUM_TOOL\SCHEMATICS_PARTS\MS_CONNECTOR_Library.schlib; Mfr_name: FCI; Mfr_part_number: 10029449-001RLF; Mistral Part No: 150010050001-R; Package: SMD; Part_type: CONNECTOR\HDMI; Project: SHIVA; RoHS: RoHS; Temperature: -20°C+85°C; Tolerance: NA; Voltage: NA; Wattage: NA; Weight: 2700mg; Datasheet: Y:\MIS_DATABASE\DATASHEETS\CONNECTORS\10029449-001RLF.PDF
R61 = RESISTOR: RES 4.7K 1/20W 5% 0201; Chkd/date: MANIRAJA/200921; Crtd /date: ALVY/200921; Custom_Duty: 15%; Customs_HS_Code: 85332119; Distributor_name: DIGIKEY; Distributor_part_number: 311-4.7KNCT-ND; Footprint Path: Y:\MIS_DATABASE\Library\ALTIUM_TOOL\PCB_FOOTPRINTS\Altium_Footprint_Lib.PcbLib; Height: 0.26MM; Library Path: Y:\MIS_DATABASE\Library\ALTIUM_TOOL\SCHEMATICS_PARTS\MS_DISCRETE_Library.schlib; Mfr_name: YAGEO AMERICA; Mfr_part_number: RC0201JR-074K7L; Mistral Part No: 110021090007-R; Package: 0201; Part_type: RESISTORS\FIXED; Project: TI_AM62x SKEVM_BRD; RoHS: RoHS; Temperature: -55°C+125°C; Tolerance: 5%; Voltage: NA; Wattage: 1/20W; Weight: 0.17mg; Datasheet: Y:\MIS_DATABASE\DATASHEETS\RESISTORS\RCXXXXL-SER_MAR18.PDF
R316 R323 = RESISTOR: RES 2.2K 1/16W 5% 0402; Chkd/date: NAVEED/150714; Crtd /date: VASANTHA/240614; Custom_Duty: 15%; Customs_HS_Code: 85332119; Distributor_name: DIGIKEY; Distributor_part_number: 541-2.2KJCT-ND; Footprint Path: Y:\MIS_DATABASE\Library\ALTIUM_TOOL\PCB_FOOTPRINTS\Altium_Footprint_Lib.PcbLib; Height: 0.40MM; Library Path: Y:\MIS_DATABASE\Library\ALTIUM_TOOL\SCHEMATICS_PARTS\MS_DISCRETE_Library.schlib; Mfr_name: VISHAY; Mfr_part_number: CRCW04022K20JNED; Mistral Part No: 110010120018-R; Package: 0402; Part_type: RESISTORS\FIXED; Project: AEGIS_POM; RoHS: RoHS; Temperature: -55°C+155°C; Tolerance: 5%; Voltage: NA; Wattage: 1/16W; Weight: 0.65mg; Datasheet: Y:\MIS_DATABASE\DATASHEETS\RESISTORS\CRCW0603.PDF
R326 = RESISTOR: RES 10K 1/16W 5% 0402; Chkd/date: MANIRAJA/120219; Crtd /date: MANIRAJA/120219; Custom_Duty: 15%; Customs_HS_Code: 85332119; Distributor_name: DIGIKEY; Distributor_part_number: 541-10KJCT-ND; Footprint Path: Y:\MIS_DATABASE\Library\ALTIUM_TOOL\PCB_FOOTPRINTS\Altium_Footprint_Lib.PcbLib; Height: 0.40MM; Library Path: Y:\MIS_DATABASE\Library\ALTIUM_TOOL\SCHEMATICS_PARTS\MS_DISCRETE_Library.schlib; Mfr_name: VISHAY; Mfr_part_number: CRCW040210K0JNED; Mistral Part No: 110011060021-R; Package: 0402; Part_type: RESISTORS\FIXED; Project: NEXTNAV_ORBIT_MODULE; RoHS: RoHS; Temperature: -55°C+155°C; Tolerance: 5%; Voltage: NA; Wattage: 1/16W; Weight: 0.65mg; Datasheet: Y:\MIS_DATABASE\DATASHEETS\RESISTORS\CRCW0603.PDF
R327 = RESISTOR: RES 7.5K 1/16W 5% 0402; Chkd/date: MAZHAR/280108; Crtd /date: USMAN/280108; Custom_Duty: 15%; Customs_HS_Code: 85332119; Distributor_name: DIGIKEY; Distributor_part_number: 541-7.5KJCT-ND; Footprint Path: Y:\MIS_DATABASE\Library\ALTIUM_TOOL\PCB_FOOTPRINTS\Altium_Footprint_Lib.PcbLib; Height: 0.40MM; Library Path: Y:\MIS_DATABASE\Library\ALTIUM_TOOL\SCHEMATICS_PARTS\MS_DISCRETE_Library.schlib; Mfr_name: VISHAY; Mfr_part_number: CRCW04027K50JNED; Mistral Part No: 110009031092-R; Package: 0402; Part_type: RESISTORS\FIXED; Project: TELEMETRY ENCODER; RoHS: RoHS; Temperature: -55°C+155°C; Tolerance: 5%; Voltage: NA; Wattage: 1/16W; Weight: 0.65mg; Datasheet: Y:\MIS_DATABASE\DATASHEETS\RESISTORS\CRCW0603.PDF
U10 = SII9022ACNU_QFN72: IC HDMI TRANSMITTER QFN72; Chkd/date: MANIRAJA/270818; Crtd /date: MUDDU/310510; Custom_Duty: 15%; Customs_HS_Code: 85423100; Distributor_name: NA; Distributor_part_number: NA; Footprint Path: Y:\MIS_DATABASE\Library\ALTIUM_TOOL\PCB_FOOTPRINTS\Altium_Footprint_Lib.PcbLib; Height: 0.90MM; Library Path: Y:\MIS_DATABASE\Library\ALTIUM_TOOL\SCHEMATICS_PARTS\MS_COMBINATIONAL_Library.schlib; Library Ref: SiI9022ACNU_QFN72; Mfr_name: SILICON IMAGE; Mistral Part No: 141010060001; Package: QFN72; Part_type: ICS\DIGITAL\PERIPHERAL; Project: CENTAURUS; RoHS: NA; Temperature: -20°C+85°C; Tolerance: NA; Voltage: NA; Wattage: NA; Weight: NA; Datasheet: Y:\MIS_DATABASE\DATASHEETS\ICS\DIGITAL\PERIPHERAL\SiI9022.PDF
U50 = TPD12S016PW_TSSOP24: IC HDMI COMPANION CHIP WITH I2C LEVEL SHIFTING,12-CH ESD TSSOP24; Chkd/date: MANIRAJA/110917; Crtd /date: BAVISH/180811; Custom_Duty: 15%; Customs_HS_Code: 85423100; Distributor_name: DIGIKEY; Distributor_part_number: 296-29690-1-ND; Height: 1.20MM; Mfr_name: TEXAS INSTRUMENTS; Mistral Part No: 141011080021-R; Package: TSSOP24; Part_type: ICS\INTERFACE; Project: DM385EVM_BASE-BOARD; RoHS: RoHS; Temperature: -40°C+85°C; Tolerance: NA; Voltage: NA; Wattage: NA; Weight: 212mg; Datasheet: Y:\MIS_DATABASE\DATASHEETS\ICS\INTERFACE\TPD12S016.PDF
U12 = AM62-EVM_BGA425: IC AM62 SoC MICROPROCESSOR BGA425; Chkd/date: ALVY/110621; Crtd /date: MANIRAJA/110621; Custom_Duty: 15%; Customs_HS_Code: 85423100; Distributor_name: NA; Distributor_part_number: NA; Footprint Path: Y:\MIS_DATABASE\Library\ALTIUM_TOOL\PCB_FOOTPRINTS\Altium_Footprint_Lib.PcbLib; Height: 0.65MM; Library Path: Y:\MIS_DATABASE\Library\ALTIUM_TOOL\SCHEMATICS_PARTS\MS_MICROPROCESSOR_Library.schlib; Mfr_name: TEXAS INSTRUMENTS; Mistral Part No: 141221060001; Package: BGA425; Part_type: ICS\DIGITAL\MICROPROCESSOR; Project: AM62_EVM_BRD; RoHS: NA; Temperature: NA; Tolerance: NA; Voltage: NA; Wattage: NA; Weight: NA; Datasheet: Y:\MIS_DATABASE\DATASHEETS\ICS\DIGITAL\MICROCONTROLLER\AM62-SoC_SVB.PDF

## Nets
AGND_AUD: C137.2 C140.2 C145.2 C146.2 C405.2 C406.2 C410.2 C411.2 FL12.1 J12.4 TP65.1(TP) U66.15(AVSS_ADC) U66.20(DRVSS.1) U66.21(DRVSS.2) U66.26(AVSS_DAC) U66.49(TPAD)
DGND: C20.1 C199.2 C200.2 C201.2 C204.2 C207.2 C209.2 C211.2 C212.2 C213.2 C217.2 C219.2 C223.2 C225.2 C229.2 C230.2 C231.2 C232.2 C248.1 C323.2 C384.2 C386.2 C388.2 C393.2 C394.2 C421.2 FL12.2 FL17.1 J5.2 J5.5 J5.8 J5.11 J5.17 R62.2 R172.2 R173.2 R287.1 R326.2 R327.2 R373.1 R390.1 R474.1 R487.1 U7.2(GND) U10.43(CGND) U10.55(RSVDL) U10.57(IOGND) U10.63(AGND) U10.70(VDDQ) U10.73(PAD) U50.6(GND1) U50.14(GND2) U50.19(GND3) U54.3(GND) U59.2(GND) U66.42(DVSS) U66.43(SELECT) U71.3(GND) ; also on sheet 1 10 11 12 13 14 15 16 17 18 19 20 21 22 23 24 25 26 27 28 29 30 31 32 33 34 35 36 37 38 39 42 43
VCC_1V8: R446.2 ; also on sheet 12 13 14 18 19 21 25 34 37 39 42
VCC_1V8_AUD: C393.1 C394.1 R446.1 U66.36(DVDD.1)
VCC_3V3_AUD: C145.1 C146.1 C384.1 C386.1 C388.1 C405.1 C406.1 C410.1 C411.1 C421.1 R425.1 R432.1 R433.1 R469.2 R477.1 U59.4(VCC) U66.16(DRVDD.1) U66.17(DRVDD.2) U66.24(DRVDD.3) U66.25(AVDD_DAC) U66.44(IOVDD) U71.5(VCC)
VCC_3V3_SYS: C20.2 C204.1 C248.2 C323.1 FB1.2 R41.2 R314.2 R389.2 R477.2 U7.4(VCC) U50.24(VCCA) U54.5(VCC) ; also on sheet 10 12 13 14 18 19 20 22 23 24 25 26 27 29 30 31 32 33 34 35 36 37 38 39 42 43
VCC_5V0: C219.1 U50.11(VCC5V) ; also on sheet 10 11 33 36
VCC_5V0_HDMICONN: C211.1 J5.18 U50.13(5V_OUT)
VDD_1V2: C201.1 C232.1 FB2.2 FB3.2 ; also on sheet 13 14
AUD_RSTn: R487.2 U66.33(~{RESET}) U71.4(Y)
AUDIO_EXT_REFCLK1: R34.1 U7.3(OUTPUT) ; also on sheet 33
AUDIO_MSTRCLK: R438.1 U66.37(MCLK)
GPIO_AUD_RSTn: R469.1 R474.2 U71.1(A) ; also on sheet 39
GPIO_HDMI_RSTn: R389.1 R390.2 U54.1(A) ; also on sheet 39
HDMI_AUDD1: TP16.1(TP) U10.40(SD1)
HDMI_AUDD2: TP14.1(TP) U10.39(SD2)
HDMI_AUDD3: TP88.1(TP) U10.37(SD3)
HDMI_CEC: U10.71(CEC_A) U50.1(CEC_A)
HDMI_CEC_D: TP18.1(TP) U10.50(CEC_D)
HDMI_CLK+: J5.10 U10.59(TXC+) U50.16(CLK+)
HDMI_CLK-: J5.12 U10.58(TXC-) U50.15(CLK-)
HDMI_CONN_I2CSCL: J5.15 U50.8(SCL_B)
HDMI_CONN_I2CSDA: J5.16 U50.9(SDA_B)
HDMI_CONNCEC: J5.13 U50.7(CEC_B)
HDMI_EARTH: FL17.2 J5.20 J5.21 J5.22 J5.23
HDMI_EXTSWING: R327.1 U10.56(EXT_SWING)
HDMI_HPD: R326.1 U10.54(HPD) U50.4(HPD_A)
HDMI_I2C_SCL: R323.2 U10.49(DSCL) U50.2(SCL_A)
HDMI_I2C_SDA: R316.2 U10.48(DSDA) U50.3(SDA_A)
HDMI_INTn: R325.2 U10.52(INT) ; also on sheet 39
HDMI_MSTRCLK: R34.2 U10.38(MCLK)
HDMI_PCLK: R60.2 U10.22(IDCK)
HDMI_RSTn: R373.2 U10.51(RESET#) U54.4(Y)
HDMI_TX0+: J5.7 U10.62(TX0+) U50.18(D0+)
HDMI_TX0-: J5.9 U10.61(TX0-) U50.17(D0-)
HDMI_TX1+: J5.4 U10.65(TX1+) U50.21(D1+)
HDMI_TX1-: J5.6 U10.64(TX1-) U50.20(D1-)
HDMI_TX2+: J5.1 U10.68(TX2+) U50.23(D2+)
HDMI_TX2-: J5.3 U10.67(TX2-) U50.22(D2-)
HDMICONN_HPD: J5.19 U50.10(HPD_B)
HPLOUT: C416.2 J12.2
HPLOUT_C: C416.1 U66.18(HPLOUT)
HPROUT: C417.2 J12.3
HPROUT_C: C417.1 U66.23(HPROUT)
LINE1L+: C397.1 TP56.1(TP)
LINE1L+_C: C397.2 U66.3(LINE1L+)
LINE1R+: C399.1 TP59.1(TP)
LINE1R+_C: C399.2 U66.5(LINE1R+)
MCASP1_ACLKX_AUD: TP54.1(TP) U66.38(BCLK) ; also on sheet 39
MCASP1_ACLKX_HDMI: U10.45(SCK) ; also on sheet 39
MCASP1_AFSX_AUD: TP50.1(TP) U66.39(WCLK) ; also on sheet 39
MCASP1_AFSX_HDMI: U10.44(WS) ; also on sheet 39
MCASP1_AXR0_AUD: TP55.1(TP) U66.40(DIN) ; also on sheet 39
MCASP1_AXR0_HDMI: U10.41(SD0) ; also on sheet 39
MCASP1_AXR2_AUD: R437.1 TP49.1(TP) ; also on sheet 39
MFP0: R172.1 R433.2 U66.45(MFP0)
MFP1: R173.1 R432.2 U66.46(MFP1)
MFP2: TP52.1(TP) U66.47(MFP2)
MFP3: TP53.1(TP) U66.48(MFP3)
MIC_IN: C412.1 J12.1 R479.1 U66.12(MICDET)
RESETSTATz: U54.2(B) U71.2(B) ; also on sheet 13 19 20 21 23 24 27 32 33 37 39 42
SOC_I2C1_SCL: R440.1 U10.1(CSCL) ; also on sheet 14 22 26 39 42
SOC_I2C1_SDA: R439.1 U10.2(CSDA) ; also on sheet 14 22 26 39 42
SoC_VOUT0_DATA0: U10.32(D0) U12.U22(VOUT0_DATA0)
SoC_VOUT0_DATA1: U10.31(D1) U12.V24(VOUT0_DATA1)
SoC_VOUT0_DATA2: U10.30(D2) U12.W25(VOUT0_DATA2)
SoC_VOUT0_DATA3: U10.29(D3) U12.W24(VOUT0_DATA3)
SoC_VOUT0_DATA4: U10.28(D4) U12.Y25(VOUT0_DATA4)
SoC_VOUT0_DATA5: U10.27(D5) U12.Y24(VOUT0_DATA5)
SoC_VOUT0_DATA6: U10.25(D6) U12.Y23(VOUT0_DATA6)
SoC_VOUT0_DATA7: U10.24(D7) U12.AA25(VOUT0_DATA7)
SoC_VOUT0_DATA8: U10.23(D8) U12.V21(VOUT0_DATA8)
SoC_VOUT0_DATA9: U10.20(D9) U12.W21(VOUT0_DATA9)
SoC_VOUT0_DATA10: U10.19(D10) U12.V20(VOUT0_DATA10)
SoC_VOUT0_DATA11: U10.18(D11) U12.AA23(VOUT0_DATA11)
SoC_VOUT0_DATA12: U10.17(D12) U12.AB25(VOUT0_DATA12)
SoC_VOUT0_DATA13: U10.16(D13) U12.AA24(VOUT0_DATA13)
SoC_VOUT0_DATA14: U10.15(D14) U12.Y22(VOUT0_DATA14)
SoC_VOUT0_DATA15: U10.14(D15) U12.AA21(VOUT0_DATA15)
SoC_VOUT0_DATA16: U10.13(D16) ; also on sheet 32
SoC_VOUT0_DATA17: U10.11(D17) ; also on sheet 32
SoC_VOUT0_DATA18: U10.10(D18) ; also on sheet 32
SoC_VOUT0_DATA19: U10.9(D19) ; also on sheet 32
SoC_VOUT0_DATA20: U10.8(D20) ; also on sheet 32
SoC_VOUT0_DATA21: U10.7(D21) ; also on sheet 32
SoC_VOUT0_DATA22: U10.6(D22) ; also on sheet 32
SoC_VOUT0_DATA23: U10.4(D23) ; also on sheet 32
SoC_VOUT0_DE: U10.33(DE) U12.Y20(VOUT0_DE)
SoC_VOUT0_HSYNC: U10.34(HSYNC) U12.AB24(VOUT0_HSYNC)
SoC_VOUT0_PCLK: R60.1 U12.AC24(VOUT0_PCLK)
SoC_VOUT0_VSYNC: U10.35(VSYNC) U12.AC25(VOUT0_VSYNC)
VHDMI_AVCC_1V2: C229.1 C230.1 C231.1 FB3.1 U10.60(AVCC12_1) U10.66(AVCC12_2)
VHDMI_CVCC_1V2: C200.1 C207.1 C209.1 C213.1 C217.1 C225.1 FB2.1 U10.5(CVCC12_1) U10.12(CVCC12_2) U10.26(CVCC12_3) U10.42(CVCC12_4) U10.47(CVCC12_5) U10.53(CVCC12_6)
VHDMI_IOVCC_3V3: C199.1 C212.1 C223.1 FB1.1 R61.1 R316.1 R323.1 R325.1 U10.3(IOVCC1) U10.21(IOVCC2) U10.46(IOVCC3)
N16927060: R61.2 U10.72(CI2CA)
N16927228: R62.1 U10.69(IO_SEL)
N16927289: R287.2 U10.36(SPDIF)
N16929458: TP63.1(TP) U66.7(LINE2L+)
N16929460: TP62.1(TP) U66.8(LINE2L-)
N16929474: R437.2 U66.41(DOUT)
N16929699: C137.1 U66.4(LINE1L-)
N16929703: C140.1 U66.6(LINE1R-)
N16929744: TP67.1(TP) U66.19(HPLCOM)
N16929747: TP66.1(TP) U66.22(HPRCOM)
N16929749: TP91.1(TP) U66.35(GPIO1)
N16929751: TP93.1(TP) U66.34(GPIO2)
N17285208: R314.1 U50.5(LS_OE) U50.12(CT_HPD)
N17498937: R439.2 U66.2(SDA)
N17498940: R440.2 U66.1(SCL)
N18736007: C412.2 U66.14(MIC3R)
N18736028: R479.2 U66.13(MICBIAS)
N20174887: R425.2 U59.1(INH)
N20174906: R438.2 U59.3(OUTPUT)
N20175146: R41.1 U7.1(INH)

Not connected (* = marked no-connect by the designer): J5 14*; U66 9(LINE2R+)* 10(LINE2R-)* 11(MIC3L)* 27(MONO_LO+)* 28(MONO_LO-)* 29(LEFT_LO+)* 30(LEFT_LO-)* 31(RIGHT_LO+)* 32(RIGHT_LO-)*

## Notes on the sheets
sheet 40
- AUDIO CODEC
- Silk: LINE IN
- MIC + HPHONE
- D-Note:-
  Add a bulk cap 1 uF
- I2C ADDRESS: 0x1B
- AUDIO CODEC RESET
- CODEC I2C ADDRESS SELECTION
- D-Note:-
  Add a series resistor to the GPIO
  input for isolation or testing
  Refer SK-AM62P-LP schematics
- MFP0
- MFP1
- Device Address
- 0
- 0
- 0x18
- 0
- 1
- 0x19
- 1
- 0
- 0x1A
- 1
- 1
- 0x1B
sheet 41
- HDMI INTERFACE
- R-Note :-
  Verify the implementation with
  the device manufacturer
- D-Note:-
  Add an additional decap
- D-Note:-
  Add bulk caps
- HDMI ESD DEVICE
- 100E
- 100E
- 100E
- 100E
- D-Note:-
  REXT_SWING modified to
  7.5K_5%. Value changed
  for internal testing
  (Radiated Emission)
  Refer device data sheet
  for the
  recommended value
- D-Note:-
  Add a bulk cap
- D-Note:-
  TPD12S016PWR has integrated pullup or pulldown resistors on the
  I2C and HPD lines hence no external pullup or pulldown required.
- HDMI CONNECTOR
- R-Note:-
  M_CLK is not used
- CAD Note:-
  Move the net after the 0R and add a 0R
  to choose the required configuration
- I2C ADDRESS: 0x3B, 0x3F, 0x62
- Silk: HDMI
- HDMI RESET
- D-Note:-
  Add a series resistor to the GPIO
  input for isolation or testing
  Refer SK-AM62P-LP schematics
